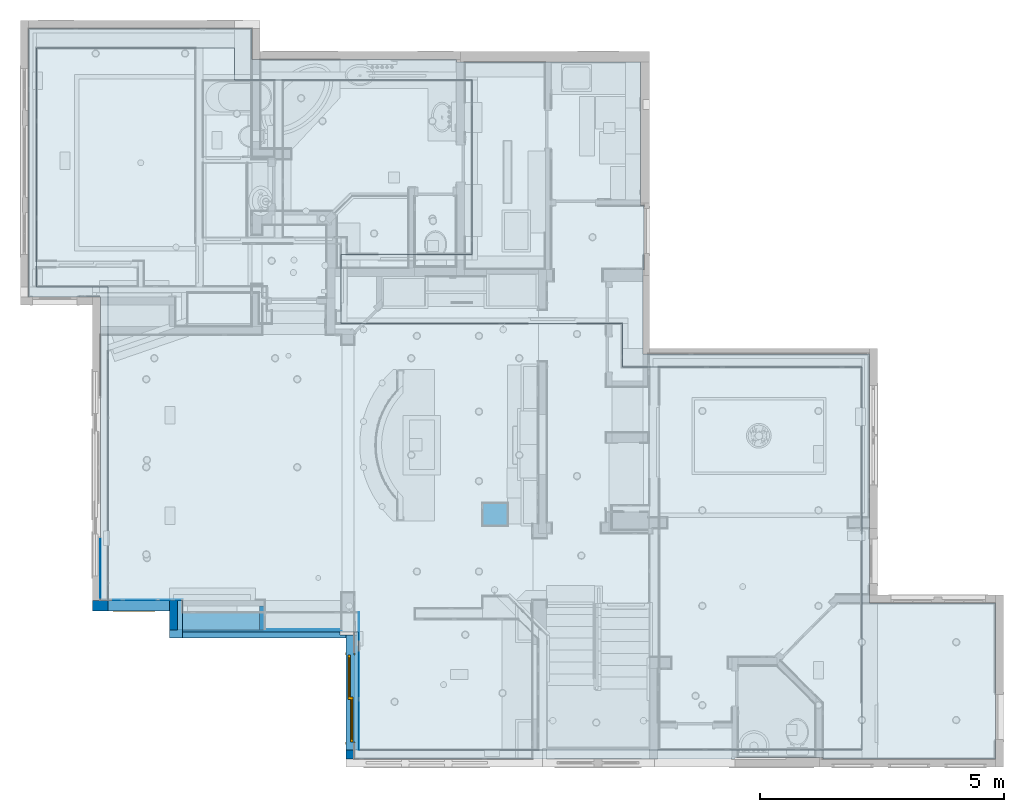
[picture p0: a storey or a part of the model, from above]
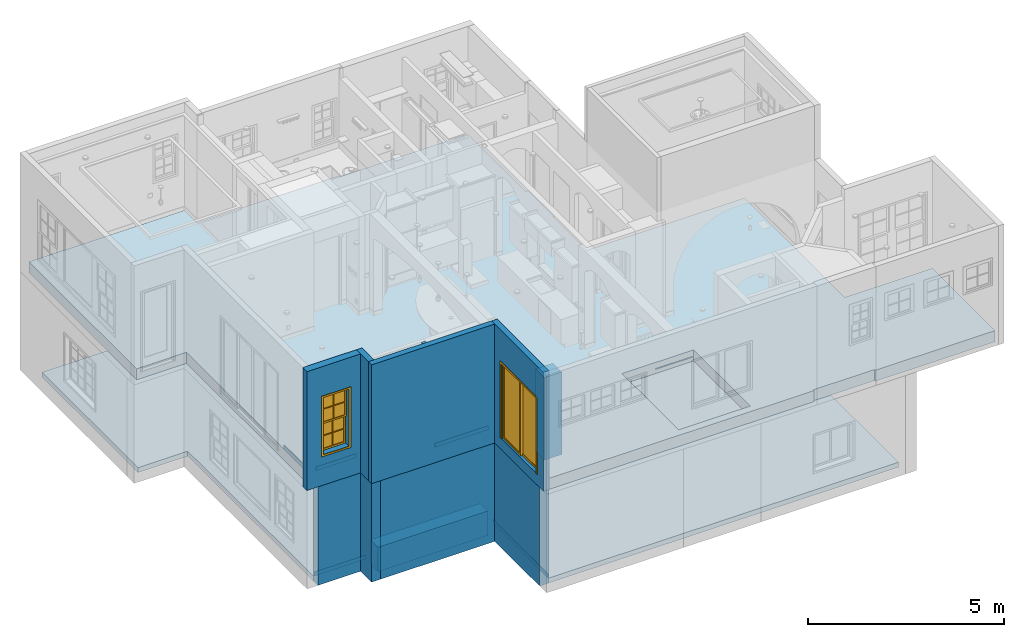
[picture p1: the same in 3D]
Properties of the parts of a building model (IFC2X3), part 1 of 2

# File
Description: ViewDefinition [CoordinationView_V2.0]
File name: Project Number
Time: 2024-05-09T19:01:35
Written by: The EXPRESS Data Manager Version 5.02.0100.07 : 28 Aug 2013
Made in: 21.1.90.15 - Exporter 21.1.90.15 - Alternate UI 21.1.90.15
Comment: STEP Physical File produced by: The EXPRESS Data Manager Version 5.02.0100.07 : 28 Aug 2013 * Module: EDMstepFileFactory/EDMstandAlone * Creation date: Thu May 09 19:01:35 2024 * Host: EDS0169-IshwarajKumbar * Database: C:\Users\User\AppData\Local\Temp\97b75f33-66e7-4dbd-bb98-ee40c45fb243\024e1fc7-9e23-4b7a-8644-b875dd77fc11\ifc * Database version: 5507 * Database creation date: Thu May 09 19:01:08 2024 * Schema: IFC2X3 * Model: DataRepository.ifc * Model creation date: Thu May 09 19:01:08 2024 * Header model: DataRepository.ifc_HeaderModel * Header model creation date: Thu May 09 19:01:08 2024 * EDMuser: sdai-user * EDMgroup: sdai-group * License ID and type: 5605 : Permanent license. Expiry date: * EDMstepFileFactory options: 020000

# IfcProject, Project Number
LongName: Project Name; Phase: Project Status

# IfcSite, Default
RefLatitude: 42, 21, 30, 344238; RefLongitude: -71, -3, -35, -194702; RefElevation: 0 ft
Pset_ProductRequirements - Category: Project Information

# IfcBuilding
Pset_BuildingCommon - NumberOfStoreys: 1
Pset_ProductRequirements - Category: Project Information

# IfcBuildingStorey: Level:1/4" Head, First floor
LongName: First floor; Elevation: 0 ft
Pset_AirSideSystemInformation - Name: First floor
Pset_ProductRequirements - Name: First floor; Category: Levels

# IfcBuildingElementProxy: Ceiling Duct:Ceiling Duct (10)
In: First floor
Type - Material: Default New Material
Type - Pset_BuildingElementProxyCommon - Reference: Ceiling Duct
Type - Pset_ProductRequirements - Category: Generic Models
Type - Pset_QuantityTakeOff - Reference: Ceiling Duct
Pset_BuildingElementProxyCommon - sets with these values: 2
Name (Ceiling Duct:Ceiling Duct:...) | Width (ft)
1502270 | 0.666667 | Pset_ProvisionForVoid - Height: 1.16667 ft; Depth: 0.0416667 ft
1502380 | 0.666667
1523142 | 0.666667
1523175 | 0.666667
1523206 | 0.666667
1523271 | 0.666667
1537971 | 0.75 | Pset_ProvisionForVoid - Height: 0.75 ft; Depth: 0.0416667 ft
1540716 | 0.666667
1568270 | 0.75
1568282 | 0.75

# IfcBuildingElementProxy: Floor Duct:Floor Duct (4)
In: First floor
Type - Material: Default New Material
Type - Pset_BuildingElementProxyCommon - Reference: Floor Duct
Type - Pset_ProductRequirements - Category: Generic Models
Type - Pset_QuantityTakeOff - Reference: Floor Duct
Pset_BuildingElementProxyCommon - sets with these values: 2
Name (Floor Duct:Floor Duct:...) | Width (ft)
1553929 | 0.666667 | Pset_ProvisionForVoid - Height: 0.666667 ft; Depth: 0.0416667 ft
1554124 | 0.666667
1580008 | 0.416667 | Pset_ProvisionForVoid - Height: 0.416667 ft; Depth: 0.0416667 ft
1580015 | 0.416667

# IfcBuildingElementProxy: Generic Models 10:Generic Models 10, Generic Models 10:Generic Models 10:1549112
In: First floor
Type - Material: Default New Material
Type - Pset_BuildingElementProxyCommon - Reference: Generic Models 10
Type - Pset_ProductRequirements - Category: Generic Models
Type - Pset_QuantityTakeOff - Reference: Generic Models 10
Pset_BuildingElementProxyCommon - sets with these values: 2
Pset_ProvisionForVoid - Width: 0.416667 ft; Height: 0.894398 ft; Depth: 0.416667 ft

# IfcBuildingElementProxy: Generic Models 11:Generic Models 11, Generic Models 11:Generic Models 11:1549126
In: First floor
Type - Material: Default New Material
Type - Pset_BuildingElementProxyCommon - Reference: Generic Models 11
Type - Pset_ProductRequirements - Category: Generic Models
Type - Pset_QuantityTakeOff - Reference: Generic Models 11
Pset_BuildingElementProxyCommon - sets with these values: 2

# IfcBuildingElementProxy: Generic Models 12:Generic Models 12, Generic Models 12:Generic Models 12:1549258
In: First floor
Type - Material: Default New Material
Type - Pset_BuildingElementProxyCommon - Reference: Generic Models 12
Type - Pset_ProductRequirements - Category: Generic Models
Type - Pset_QuantityTakeOff - Reference: Generic Models 12
Pset_BuildingElementProxyCommon - sets with these values: 2
Pset_ProvisionForVoid - Width: 1.45833 ft; Height: 6.91667 ft; Depth: 1.45833 ft

# IfcBuildingElementProxy: Generic Models 14:Generic Models 5, Generic Models 14:Generic Models 5:1550655
In: First floor
Type - Material: Default New Material
Type - Pset_BuildingElementProxyCommon - Reference: Generic Models 5
Type - Pset_ProductRequirements - Category: Generic Models
Type - Pset_QuantityTakeOff - Reference: Generic Models 5
Pset_BuildingElementProxyCommon - sets with these values: 2

# IfcBuildingElementProxy: Generic Models 15:Generic Models 15, Generic Models 15:Generic Models 15:1552585
In: First floor
Type - Material: Default New Material
Type - Pset_BuildingElementProxyCommon - Reference: Generic Models 15
Type - Pset_ProductRequirements - Category: Generic Models
Type - Pset_QuantityTakeOff - Reference: Generic Models 15
Pset_BuildingElementProxyCommon - sets with these values: 2

# IfcBuildingElementProxy: Generic Models 16:Generic Models 16, Generic Models 16:Generic Models 16:1554491
In: First floor
Type - Material: Default New Material
Type - Pset_BuildingElementProxyCommon - Reference: Generic Models 16
Type - Pset_ProductRequirements - Category: Generic Models
Type - Pset_QuantityTakeOff - Reference: Generic Models 16
Material: Default New Material, Glass
Pset_OpeningElementCommon - Reference: Generic Models 16; sets with these values: 2

# IfcBuildingElementProxy: Generic Models 20:Generic Models 20, Generic Models 20:Generic Models 20:1561079
In: First floor
Type - Material: Default New Material
Type - Pset_BuildingElementProxyCommon - Reference: Generic Models 20
Type - Pset_ProductRequirements - Category: Generic Models
Type - Pset_QuantityTakeOff - Reference: Generic Models 20
Pset_BuildingElementProxyCommon - sets with these values: 2

# IfcBuildingElementProxy: Generic Models 21:Generic Models 20, Generic Models 21:Generic Models 20:1561344
In: First floor
Type - Material: Default New Material
Type - Pset_BuildingElementProxyCommon - Reference: Generic Models 20
Type - Pset_ProductRequirements - Category: Generic Models
Type - Pset_QuantityTakeOff - Reference: Generic Models 20
Pset_BuildingElementProxyCommon - sets with these values: 2

# IfcBuildingElementProxy: Generic Models 22:Generic Models 22, Generic Models 22:Generic Models 22:1578308
In: First floor
Type - Material: Default New Material
Type - Pset_BuildingElementProxyCommon - Reference: Generic Models 22
Type - Pset_ProductRequirements - Category: Generic Models
Type - Pset_QuantityTakeOff - Reference: Generic Models 22
Pset_OpeningElementCommon - Reference: Generic Models 22; sets with these values: 2

# IfcBuildingElementProxy: Generic Models 23:Generic Models 16, Generic Models 23:Generic Models 16:1565228
In: First floor
Type - Material: Default New Material
Type - Pset_BuildingElementProxyCommon - Reference: Generic Models 16
Type - Pset_ProductRequirements - Category: Generic Models
Type - Pset_QuantityTakeOff - Reference: Generic Models 16
Pset_BuildingElementProxyCommon - sets with these values: 2
Pset_ProvisionForVoid - Width: 1.125 ft; Depth: 1.125 ft

# IfcBuildingElementProxy: Generic Models 24:Generic Models 24, Generic Models 24:Generic Models 24:1568251
In: First floor
Type - Material: Default New Material
Type - Pset_BuildingElementProxyCommon - Reference: Generic Models 24
Type - Pset_ProductRequirements - Category: Generic Models
Type - Pset_QuantityTakeOff - Reference: Generic Models 24
Pset_BuildingElementProxyCommon - sets with these values: 2
Pset_ProvisionForVoid - Width: 0.416667 ft; Depth: 0.416667 ft

# IfcBuildingElementProxy: Generic Models 25:Generic Models 23, Generic Models 25:Generic Models 23:1566142
In: First floor
Type - Material: Default New Material
Type - Pset_BuildingElementProxyCommon - Reference: Generic Models 23
Type - Pset_ProductRequirements - Category: Generic Models
Type - Pset_QuantityTakeOff - Reference: Generic Models 23
Pset_BuildingElementProxyCommon - sets with these values: 2

# IfcBuildingElementProxy: Generic Models 28:Generic Models 28, Generic Models 28:Generic Models 28:1579950
In: First floor
Type - Material: Default New Material
Type - Pset_BuildingElementProxyCommon - Reference: Generic Models 28
Type - Pset_ProductRequirements - Category: Generic Models
Type - Pset_QuantityTakeOff - Reference: Generic Models 28
Pset_BuildingElementProxyCommon - sets with these values: 2

# IfcBuildingElementProxy: Generic Models 29:Generic Models 28, Generic Models 29:Generic Models 28:1579967
In: First floor
Type - Material: Default New Material
Type - Pset_BuildingElementProxyCommon - Reference: Generic Models 28
Type - Pset_ProductRequirements - Category: Generic Models
Type - Pset_QuantityTakeOff - Reference: Generic Models 28
Pset_BuildingElementProxyCommon - sets with these values: 2

# IfcBuildingElementProxy: Generic Models 30:Generic Models 30, Generic Models 30:Generic Models 30:1590407
In: First floor
Type - Material: Default New Material
Type - Pset_BuildingElementProxyCommon - Reference: Generic Models 30
Type - Pset_ProductRequirements - Category: Generic Models
Type - Pset_QuantityTakeOff - Reference: Generic Models 30
Pset_BuildingElementProxyCommon - sets with these values: 2
Pset_ProvisionForVoid - Width: 6.91667 ft; Depth: 6.91667 ft

# IfcBuildingElementProxy: Generic Models 31:Generic Models 28, Generic Models 31:Generic Models 28:1590470
In: First floor
Type - Material: Default New Material
Type - Pset_BuildingElementProxyCommon - Reference: Generic Models 28
Type - Pset_ProductRequirements - Category: Generic Models
Type - Pset_QuantityTakeOff - Reference: Generic Models 28
Pset_BuildingElementProxyCommon - sets with these values: 2

# IfcBuildingElementProxy: Generic Models 32:Generic Models 28, Generic Models 32:Generic Models 28:1590484
In: First floor
Type - Material: Default New Material
Type - Pset_BuildingElementProxyCommon - Reference: Generic Models 28
Type - Pset_ProductRequirements - Category: Generic Models
Type - Pset_QuantityTakeOff - Reference: Generic Models 28
Pset_BuildingElementProxyCommon - sets with these values: 2

# IfcBuildingElementProxy: Generic Models 33:Generic Models 28, Generic Models 33:Generic Models 28:1590457
In: First floor
Type - Material: Default New Material
Type - Pset_BuildingElementProxyCommon - Reference: Generic Models 28
Type - Pset_ProductRequirements - Category: Generic Models
Type - Pset_QuantityTakeOff - Reference: Generic Models 28
Pset_BuildingElementProxyCommon - sets with these values: 2

# IfcBuildingElementProxy: Generic Models 34:Generic Models 28, Generic Models 34:Generic Models 28:1593320
In: First floor
Type - Material: Default New Material
Type - Pset_BuildingElementProxyCommon - Reference: Generic Models 28
Type - Pset_ProductRequirements - Category: Generic Models
Type - Pset_QuantityTakeOff - Reference: Generic Models 28
Pset_BuildingElementProxyCommon - sets with these values: 2

# IfcBuildingElementProxy: Generic Models 35:Generic Models 28, Generic Models 35:Generic Models 28:1593336
In: First floor
Type - Material: Default New Material
Type - Pset_BuildingElementProxyCommon - Reference: Generic Models 28
Type - Pset_ProductRequirements - Category: Generic Models
Type - Pset_QuantityTakeOff - Reference: Generic Models 28
Pset_BuildingElementProxyCommon - sets with these values: 2

# IfcBuildingElementProxy: Generic Models 36:Generic Models 28, Generic Models 36:Generic Models 28:1593352
In: First floor
Type - Material: Default New Material
Type - Pset_BuildingElementProxyCommon - Reference: Generic Models 28
Type - Pset_ProductRequirements - Category: Generic Models
Type - Pset_QuantityTakeOff - Reference: Generic Models 28
Pset_BuildingElementProxyCommon - sets with these values: 2
Pset_ProvisionForVoid - Width: 4.08367 ft; Depth: 4.08367 ft

# IfcBuildingElementProxy: Generic Models 37:Generic Models 37, Generic Models 37:Generic Models 37:1600293
In: First floor
Type - Material: Default New Material
Type - Pset_BuildingElementProxyCommon - Reference: Generic Models 37
Type - Pset_ProductRequirements - Category: Generic Models
Type - Pset_QuantityTakeOff - Reference: Generic Models 37
Pset_BuildingElementProxyCommon - sets with these values: 2

# IfcBuildingElementProxy: Generic Models 38:Generic Models 38, Generic Models 38:Generic Models 38:1608313
In: First floor
Type - Material: Default New Material
Type - Pset_BuildingElementProxyCommon - Reference: Generic Models 38
Type - Pset_ProductRequirements - Category: Generic Models
Type - Pset_QuantityTakeOff - Reference: Generic Models 38
Pset_BuildingElementProxyCommon - sets with these values: 2
Pset_ProvisionForVoid - Width: 0.625 ft; Height: 10.5833 ft; Depth: 0.625 ft

# IfcBuildingElementProxy: Generic Models 3:Generic Models 3, Generic Models 3:Generic Models 3:1515765
In: First floor
Type - Material: Glass
Type - Pset_BuildingElementProxyCommon - Reference: Generic Models 3
Type - Pset_ProductRequirements - Category: Generic Models
Type - Pset_QuantityTakeOff - Reference: Generic Models 3
Pset_BuildingElementProxyCommon - sets with these values: 2
Pset_ProvisionForVoid - Width: 6.83333 ft; Depth: 6.83333 ft

# IfcBuildingElementProxy: Generic Models 47:Generic Models 5, Generic Models 47:Generic Models 5:1632938
In: First floor
Type - Material: Default New Material
Type - Pset_BuildingElementProxyCommon - Reference: Generic Models 5
Type - Pset_ProductRequirements - Category: Generic Models
Type - Pset_QuantityTakeOff - Reference: Generic Models 5
Pset_BuildingElementProxyCommon - sets with these values: 2

# IfcBuildingElementProxy: Generic Models 4:Generic Models 4, Generic Models 4:Generic Models 4:1523625
In: First floor
Type - Material: Default New Material
Type - Pset_BuildingElementProxyCommon - Reference: Generic Models 4
Type - Pset_ProductRequirements - Category: Generic Models
Type - Pset_QuantityTakeOff - Reference: Generic Models 4
Pset_OpeningElementCommon - Reference: Generic Models 4; sets with these values: 2

# IfcBuildingElementProxy: Generic Models 52:Generic Models 52, Generic Models 52:Generic Models 52:1640525
In: First floor
Type - Material: Default New Material
Type - Pset_BuildingElementProxyCommon - Reference: Generic Models 52
Type - Pset_ProductRequirements - Category: Generic Models
Type - Pset_QuantityTakeOff - Reference: Generic Models 52
Pset_BuildingElementProxyCommon - sets with these values: 2
Pset_ProvisionForVoid - Width: 2.08333 ft; Depth: 2.08333 ft

# IfcBuildingElementProxy: Generic Models 56:Generic Models 56, Generic Models 56:Generic Models 56:1644916
In: First floor
Type - Material: Default New Material
Type - Pset_BuildingElementProxyCommon - Reference: Generic Models 56
Type - Pset_ProductRequirements - Category: Generic Models
Type - Pset_QuantityTakeOff - Reference: Generic Models 56
Pset_BuildingElementProxyCommon - sets with these values: 2
Pset_ProvisionForVoid - Width: 0.0833333 ft; Depth: 0.0833333 ft

# IfcBuildingElementProxy: Generic Models 59:Generic Models 59, Generic Models 59:Generic Models 59:1646296
In: First floor
Type - Material: Default New Material
Type - Pset_BuildingElementProxyCommon - Reference: Generic Models 59
Type - Pset_ProductRequirements - Category: Generic Models
Type - Pset_QuantityTakeOff - Reference: Generic Models 59
Pset_BuildingElementProxyCommon - sets with these values: 2
Pset_ProvisionForVoid - Width: 1.16667 ft; Height: 1.08333 ft; Depth: 1.16667 ft

# IfcBuildingElementProxy: Generic Models 60:Generic Models 59, Generic Models 60:Generic Models 59:1647426
In: First floor
Type - Material: Default New Material
Type - Pset_BuildingElementProxyCommon - Reference: Generic Models 59
Type - Pset_ProductRequirements - Category: Generic Models
Type - Pset_QuantityTakeOff - Reference: Generic Models 59
Pset_BuildingElementProxyCommon - sets with these values: 2
Pset_ProvisionForVoid - Width: 1.16667 ft; Height: 1.08333 ft; Depth: 1.16667 ft

# IfcBuildingElementProxy: Generic Models 61:Generic Models 61, Generic Models 61:Generic Models 61:1657220
In: First floor
Type - Material: Default New Material
Type - Pset_BuildingElementProxyCommon - Reference: Generic Models 61
Type - Pset_ProductRequirements - Category: Generic Models
Type - Pset_QuantityTakeOff - Reference: Generic Models 61
Pset_BuildingElementProxyCommon - sets with these values: 2
Pset_ProvisionForVoid - Width: 1 ft; Height: 2 ft; Depth: 1 ft

# IfcBuildingElementProxy: Generic Models 62:Generic Models 62, Generic Models 62:Generic Models 62:1670910
In: First floor
Type - Material: <Unnamed>
Type - Pset_BuildingElementProxyCommon - Reference: Generic Models 62
Type - Pset_ProductRequirements - Category: Generic Models
Type - Pset_QuantityTakeOff - Reference: Generic Models 62
Pset_OpeningElementCommon - Reference: Generic Models 62; sets with these values: 2

# IfcBuildingElementProxy: Generic Models 64:Generic Models 64, Generic Models 64:Generic Models 64:1680121
In: First floor
Type - Material: Default New Material
Type - Pset_BuildingElementProxyCommon - Reference: Generic Models 64
Type - Pset_ProductRequirements - Category: Generic Models
Type - Pset_QuantityTakeOff - Reference: Generic Models 64
Pset_BuildingElementProxyCommon - sets with these values: 2
Pset_ProvisionForVoid - Width: 0.0416667 ft; Height: 4 ft; Depth: 0.0416667 ft

# IfcBuildingElementProxy: Generic Models 65:Generic Models 65, Generic Models 65:Generic Models 65:1687296
In: First floor
Type - Material: Default New Material
Type - Pset_BuildingElementProxyCommon - Reference: Generic Models 65
Type - Pset_ProductRequirements - Category: Generic Models
Type - Pset_QuantityTakeOff - Reference: Generic Models 65
Pset_BuildingElementProxyCommon - sets with these values: 2
Pset_ProvisionForVoid - Width: 0.0833333 ft; Depth: 0.0833333 ft

# IfcBuildingElementProxy: Generic Models 66:Generic Models 66, Generic Models 66:Generic Models 66:1692336
In: First floor
Type - Material: Default New Material
Type - Pset_BuildingElementProxyCommon - Reference: Generic Models 66
Type - Pset_ProductRequirements - Category: Generic Models
Type - Pset_QuantityTakeOff - Reference: Generic Models 66
Pset_BuildingElementProxyCommon - sets with these values: 2
Pset_ProvisionForVoid - Width: 1.16667 ft; Height: 2.08333 ft; Depth: 1.16667 ft

# IfcBuildingElementProxy: Generic Models 67:Generic Models 67, Generic Models 67:Generic Models 67:1693115
In: First floor
Type - Material: Default New Material
Type - Pset_BuildingElementProxyCommon - Reference: Generic Models 67
Type - Pset_ProductRequirements - Category: Generic Models
Type - Pset_QuantityTakeOff - Reference: Generic Models 67
Pset_BuildingElementProxyCommon - sets with these values: 2
Pset_ProvisionForVoid - Width: 3.25 ft; Depth: 3.25 ft

# IfcBuildingElementProxy: Generic Models 68:Generic Models 68, Generic Models 68:Generic Models 68:1696514
In: First floor
Type - Material: Default New Material
Type - Pset_BuildingElementProxyCommon - Reference: Generic Models 68
Type - Pset_ProductRequirements - Category: Generic Models
Type - Pset_QuantityTakeOff - Reference: Generic Models 68
Pset_BuildingElementProxyCommon - sets with these values: 2
Pset_ProvisionForVoid - Width: 1.58333 ft; Height: 1.5 ft; Depth: 1.58333 ft

# IfcBuildingElementProxy: Generic Models 7:Generic Models 7, Generic Models 7:Generic Models 7:1549020
In: First floor
Type - Material: Default New Material
Type - Pset_BuildingElementProxyCommon - Reference: Generic Models 7
Type - Pset_ProductRequirements - Category: Generic Models
Type - Pset_QuantityTakeOff - Reference: Generic Models 7
Pset_BuildingElementProxyCommon - sets with these values: 2
Pset_ProvisionForVoid - Width: 0.0416667 ft; Depth: 0.0416667 ft

# IfcBuildingElementProxy: Generic Models 8:Generic Models 8, Generic Models 8:Generic Models 8:1549080
In: First floor
Type - Material: Default New Material
Type - Pset_BuildingElementProxyCommon - Reference: Generic Models 8
Type - Pset_ProductRequirements - Category: Generic Models
Type - Pset_QuantityTakeOff - Reference: Generic Models 8
Pset_BuildingElementProxyCommon - sets with these values: 2
Pset_ProvisionForVoid - Width: 0.416667 ft; Height: 0.908704 ft; Depth: 0.416667 ft

# IfcBuildingElementProxy: Generic Models 9:Generic Models 9, Generic Models 9:Generic Models 9:1549096
In: First floor
Type - Material: Default New Material
Type - Pset_BuildingElementProxyCommon - Reference: Generic Models 9
Type - Pset_ProductRequirements - Category: Generic Models
Type - Pset_QuantityTakeOff - Reference: Generic Models 9
Pset_BuildingElementProxyCommon - sets with these values: 2
Pset_ProvisionForVoid - Width: 0.416667 ft; Height: 0.908704 ft; Depth: 0.416667 ft

# IfcBuildingElementProxy: Generic_01:Generic_01 (2)
In: First floor
Type - Material: Default New Material
Type - Pset_BuildingElementProxyCommon - Reference: Generic_01
Type - Pset_ProductRequirements - Category: Generic Models
Type - Pset_QuantityTakeOff - Reference: Generic_01
Pset_BuildingElementProxyCommon - sets with these values: 2
Pset_ProvisionForVoid - Width: 1.375 ft; Height: 0.666667 ft
Name (Generic_01:Generic_01:...)
1546603 | Pset_ProvisionForVoid - Depth: 0.666667 ft
1593018

# IfcBuildingElementProxy: Generic_02:Generic_02 (4)
In: First floor
Type - Material: Default New Material
Type - Pset_BuildingElementProxyCommon - Reference: Generic_02
Type - Pset_ProductRequirements - Category: Generic Models
Type - Pset_QuantityTakeOff - Reference: Generic_02
Pset_BuildingElementProxyCommon - sets with these values: 2
Pset_ProvisionForVoid - Height: 0.145833 ft
Name (Generic_02:Generic_02:...) | Width (ft) | Depth (ft)
1545830 | 1.16667 | 0.0208333
1551174 | 1.16667
1565230 | 0.75 | 0.0208333
1574967 | 0.75 | 0.0208333

# IfcBuildingElementProxy: Generic_03:Generic_03, Generic_03:Generic_03:1589796
In: First floor
Type - Material: Default New Material
Type - Pset_BuildingElementProxyCommon - Reference: Generic_03
Type - Pset_ProductRequirements - Category: Generic Models
Type - Pset_QuantityTakeOff - Reference: Generic_03
Pset_BuildingElementProxyCommon - sets with these values: 2
Pset_ProvisionForVoid - Width: 0.416667 ft; Height: 0.416667 ft; Depth: 0.0416667 ft

# IfcBuildingElementProxy: Specialty Equipment 1:Specialty Equipment 1, Specialty Equipment 1:Specialty Equipment 1:1546123
In: First floor
Type - Material: Default New Material
Type - Pset_BuildingElementProxyCommon - Reference: Specialty Equipment 1
Type - Pset_ProductRequirements - Category: Specialty Equipment
Type - Pset_QuantityTakeOff - Reference: Specialty Equipment 1
Pset_BuildingElementProxyCommon - sets with these values: 2
Pset_ProvisionForVoid - Width: 0.230472 ft; Depth: 0.230472 ft

# IfcBuildingElementProxy: Specialty Equipment 2:Specialty Equipment 2, Specialty Equipment 2:Specialty Equipment 2:1698001
In: First floor
Type - Material: Default New Material
Type - Pset_BuildingElementProxyCommon - Reference: Specialty Equipment 2
Type - Pset_ProductRequirements - Category: Specialty Equipment
Type - Pset_QuantityTakeOff - Reference: Specialty Equipment 2
Pset_BuildingElementProxyCommon - sets with these values: 2

# IfcBuildingElementProxy: Specialty Equipment_1:Specialty Equipment_1 (12)
In: First floor
Type - Material: Default New Material
Type - Pset_BuildingElementProxyCommon - Reference: Specialty Equipment_1
Type - Pset_ProductRequirements - Category: Specialty Equipment
Type - Pset_QuantityTakeOff - Reference: Specialty Equipment_1
Pset_BuildingElementProxyCommon - sets with these values: 2
Name (Specialty Equipment_1:Specialty Equipment_1:...) | Width (ft) | Height (ft) | Depth (ft)
1534345 | 0.5 | 0.416667 | 0.416667
1593358 | 4 | 2.83333 | 2.83333
1623707 | 0.208333 | 0.0416667 | 0.0416667
1643836 | 0.5 | 0.333333 | 0.333333
1644112 | 0.5 | 0.666667 | 0.666667
1644243 | 0.166667 | 0.166667 | 0.166667
1645875 | 0.5 | 0.375 | 0.375
1649110 | 2.16667 | 3.33333 | 3.33333
1649419 | 2.16667 | 3.33333
1653499 | 0.166667 | 0.416667 | 0.416667
1653652 | 0.666667 | 0.416667 | 0.416667
1654167 | 2 | 2.45833 | 2.45833

# IfcBuildingElementProxy: Specialty Equipment_2:Specialty Equipment_2 (4)
In: First floor
Type - Material: Default New Material
Type - Pset_BuildingElementProxyCommon - Reference: Specialty Equipment_2
Type - Pset_ProductRequirements - Category: Specialty Equipment
Type - Pset_QuantityTakeOff - Reference: Specialty Equipment_2
Pset_BuildingElementProxyCommon - sets with these values: 2
Name (Specialty Equipment_2:Specialty Equipment_2:...) | Width (ft) | Height (ft) = Depth (ft)
1590512 | 3.16667 | 5.75
1593223 | 2.75 | 0.916667
1593226 | 2.75 | 2.33333
1593228 | 2.75 | 1.58333

# IfcBuildingElementProxy: Specialty Equipment_4:Specialty Equipment_4 (6)
In: First floor
Type - Material: Default New Material
Type - Pset_BuildingElementProxyCommon - Reference: Specialty Equipment_4
Type - Pset_ProductRequirements - Category: Specialty Equipment
Type - Pset_QuantityTakeOff - Reference: Specialty Equipment_4
Pset_BuildingElementProxyCommon - sets with these values: 2
Name (Specialty Equipment_4:Specialty Equipment_4:...)
1534789 | Pset_ProvisionForVoid - Width: 0.0416667 ft; Depth: 0.0416667 ft
1535804
1540086
1559416
1576774 | Pset_ProvisionForVoid - Width: 0.0416667 ft; Depth: 0.0416667 ft
1577019

# IfcBuildingElementProxy: Switch 15:Switch 15 (9)
In: First floor
Type - Material: Default New Material
Type - Pset_BuildingElementProxyCommon - Reference: Switch 15
Type - Pset_ProductRequirements - Category: Electrical Fixtures
Type - Pset_QuantityTakeOff - Reference: Switch 15
Pset_BuildingElementProxyCommon - sets with these values: 2
Name (Switch 15:Switch 15:...)
1509897 | Pset_ProvisionForVoid - Width: 0.291667 ft; Height: 0.416667 ft; Depth: 0.291667 ft
1543753
1543996
1566214
1568121
1590492
1590504 | Pset_ProvisionForVoid - Width: 0.291667 ft; Height: 0.0416667 ft; Depth: 0.291667 ft
1592945
1593269

# IfcBuildingElementProxy: Switch 18:Switch 18 (4)
In: First floor
Type - Material: Default New Material
Type - Pset_BuildingElementProxyCommon - Reference: Switch 18
Type - Pset_ProductRequirements - Category: Electrical Fixtures
Type - Pset_QuantityTakeOff - Reference: Switch 18
Pset_BuildingElementProxyCommon - sets with these values: 2
Name (Switch 18:Switch 18:...)
1572272 | Pset_ProvisionForVoid - Width: 0.416667 ft; Height: 0.291667 ft; Depth: 0.416667 ft
1579968
1590443
1590503 | Pset_ProvisionForVoid - Width: 0.416667 ft; Height: 0.0416667 ft; Depth: 0.416667 ft

# IfcBuildingElementProxy: Switch 1:Switch 1 (37)
In: First floor
Type - Material: Default New Material
Type - Pset_BuildingElementProxyCommon - Reference: Switch 1
Type - Pset_ProductRequirements - Category: Electrical Fixtures
Type - Pset_QuantityTakeOff - Reference: Switch 1
Pset_BuildingElementProxyCommon - sets with these values: 2
Name (Switch 1:Switch 1:...) | Width (ft) | Height (ft)
1500248 | 0.291667 | 0.416667 | Pset_ProvisionForVoid - Depth: 0.416667 ft
1500756 | 0.291667 | 0.416667
1501134 | 0.291667 | 0.416667
1501219 | 0.291667 | 0.416667
1501973 | 0.291667 | 0.416667
1508420 | 0.291667 | 0.416667
1533359 | 0.291667 | 0.416667
1534123 | 0.291667 | 0.416667
1535636 | 0.291667 | 0.416667
1536600 | 0.291667 | 0.416667
1538305 | 0.291667 | 0.416667
1538381 | 0.291667 | 0.416667
1540579 | 0.291667 | 0.416667
1543512 | 0.291667 | 0.416667
1544074 | 0.291667 | 0.416667
1544209 | 0.291667 | 0.416667
1544240 | 0.291667 | 0.416667
1544276 | 0.291667 | 0.416667
1544526 | 0.291667 | 0.416667
1544649 | 0.291667 | 0.416667
1544737 | 0.291667 | 0.416667
1546165 | 0.291667 | 0.416667
1546320 | 0.291667 | 0.416667
1551175 | 0.291667 | 0.416667
1551178 | 0.291667 | 0.416667
1551225 | 0.291667 | 0.416667
1551419 | 0.291667 | 0.416667
1556863 | 0.291667 | 0.416667
1557131 | 0.291667 | 0.416667
1578468 | 0.291667 | 0.416667
1578781 | 0.291667 | 0.416667
1579326 | 0.291667 | 0.416667
1590427 | 0.291667 | 0.416667
1590428 | 0.291667 | 0.416667
1590429 | 0.291667 | 0.416667
1590490 | 0.458333 | 0.25 | Pset_ProvisionForVoid - Depth: 0.25 ft
1590499 | 0.458333 | 0.25

# IfcBuildingElementProxy: Switch 20:Switch 20, Switch 20:Switch 20:1509279
In: First floor
Type - Material: Default New Material
Type - Pset_BuildingElementProxyCommon - Reference: Switch 20
Type - Pset_ProductRequirements - Category: Electrical Fixtures
Type - Pset_QuantityTakeOff - Reference: Switch 20
Pset_BuildingElementProxyCommon - sets with these values: 2
Pset_ProvisionForVoid - Width: 0.416667 ft; Height: 0.583333 ft; Depth: 0.416667 ft

# IfcBuildingElementProxy: Switch 22:Switch 22 (8)
In: First floor
Type - Material: Default New Material
Type - Pset_BuildingElementProxyCommon - Reference: Switch 22
Type - Pset_ProductRequirements - Category: Electrical Fixtures
Type - Pset_QuantityTakeOff - Reference: Switch 22
Pset_BuildingElementProxyCommon - sets with these values: 2
Name (Switch 22:Switch 22:...)
1507004 | Pset_ProvisionForVoid - Width: 0.416667 ft; Height: 0.708333 ft; Depth: 0.416667 ft
1545878
1547098
1556649
1568123
1571976
1579429
1590430

# IfcBuildingElementProxy: Switch 3:Switch 3 (10)
In: First floor
Type - Material: Default New Material
Type - Pset_BuildingElementProxyCommon - Reference: Switch 3
Type - Pset_ProductRequirements - Category: Electrical Fixtures
Type - Pset_QuantityTakeOff - Reference: Switch 3
Pset_BuildingElementProxyCommon - sets with these values: 2
Name (Switch 3:Switch 3:...)
1535327 | Pset_ProvisionForVoid - Width: 0.416667 ft; Height: 0.291667 ft; Depth: 0.416667 ft
1536376
1538126
1543306
1546375
1551740
1565232
1565233
1575068
1578659

# IfcBuildingElementProxy: Switch 4:Switch 4 (50)
In: First floor
Type - Material: Default New Material
Type - Pset_BuildingElementProxyCommon - Reference: Switch 4
Type - Pset_ProductRequirements - Category: Electrical Fixtures
Type - Pset_QuantityTakeOff - Reference: Switch 4
Pset_BuildingElementProxyCommon - sets with these values: 2
Name (Switch 4:Switch 4:...)
1499978 | Pset_ProvisionForVoid - Width: 0.416667 ft; Height: 0.291667 ft; Depth: 0.416667 ft
1500459
1501395
1501552
1501702
1506937
1506939
1506940
1507204
1507495
1507695
1508319
1508593
1508731
1508896
1509063
1509492
1509675
1533098
1534947
1535218
1535815
1536016
1536137
1538750
1540161
1540484
1543122
1545832
1547252
1551177
1551179
1551181
1551743
1553709
1553844
1554188
1556535
1556783
1565183
1565231
1574969
1577151
1579085
1579500
1580010
1580013
1580019
1594570
1594822

# IfcBuildingElementProxy: Switch 6:Switch 6 (14)
In: First floor
Type - Material: Default New Material
Type - Pset_BuildingElementProxyCommon - Reference: Switch 6
Type - Pset_ProductRequirements - Category: Electrical Fixtures
Type - Pset_QuantityTakeOff - Reference: Switch 6
Pset_BuildingElementProxyCommon - sets with these values: 2
Name (Switch 6:Switch 6:...)
1533406 | Pset_ProvisionForVoid - Width: 0.416667 ft; Height: 0.416667 ft; Depth: 0.416667 ft
1534238
1537489
1551356
1553510
1556968
1559630
1560495
1565185
1568283
1569646
1575067
1579565
1590501

# IfcBuildingElementProxy: Wall Duct:Wall Duct (5)
In: First floor
Type - Material: Default New Material
Type - Pset_BuildingElementProxyCommon - Reference: Wall Duct
Type - Pset_ProductRequirements - Category: Generic Models
Type - Pset_QuantityTakeOff - Reference: Wall Duct
Pset_BuildingElementProxyCommon - sets with these values: 2
Name (Wall Duct:Wall Duct:...) | Width (ft) | Height (ft) | Depth (ft)
1532870 | 2.75 | 0.583333 | 0.583333
1540217 | 1 | 0.666667 | 0.666667
1560153 | 2.66667 | 0.833333 | 0.833333
1593266 | 1.375 | 0.416667 | 0.416667
1653343 | 2.75 | 0.583333

# IfcBuildingElementProxy: Wall void 1 :Wall void 1, Wall void 1 :Wall void 1:1651944
In: First floor
Type - Material: Default New Material
Type - Pset_BuildingElementProxyCommon - Reference: Wall void 1
Type - Pset_ProductRequirements - Category: Generic Models
Type - Pset_QuantityTakeOff - Reference: Wall void 1
Pset_OpeningElementCommon - Reference: Wall void 1; sets with these values: 2

# IfcColumn: M_Rectangular Column:475 x 610mm, M_Rectangular Column:475 x 610mm:1609656
In: First floor
Type - PredefinedType: COLUMN; Material: Default New Material
Type - Pset_ColumnCommon - IsExternal: no; Reference: 475 x 610mm
Type - Pset_ProductRequirements - Category: Columns
Type - Pset_QuantityTakeOff - Reference: 475 x 610mm
Type - Pset_ReinforcementBarPitchOfColumn - Reference: 475 x 610mm
Pset_QuantityTakeOff - sets with these values: 2

# IfcCovering: Compound Ceiling:Ceiling_1.5", Compound Ceiling:Ceiling_1.5":1575162
In: First floor
Type - PredefinedType: CEILING
Type - Pset_CoveringCommon - Reference: Ceiling_1.5"; TotalThickness: 0.125 ft
Type - Pset_ElementShading - Roughness: 1 ft
Type - Pset_ProductRequirements - Category: Ceilings
Type - Pset_QuantityTakeOff - Reference: Ceiling_1.5"
Classification: C3030210 Suspended Ceilings - Acoustical (Uniformat); Material: Default New Material 0.125 ft

# IfcCovering: Compound Ceiling:Ceiling_1.5" 1, Compound Ceiling:Ceiling_1.5" 1:1579975
In: First floor
Type - PredefinedType: CEILING
Type - Pset_CoveringCommon - Reference: Ceiling_1.5" 1; TotalThickness: 0.125 ft
Type - Pset_ElementShading - Roughness: 1 ft
Type - Pset_ProductRequirements - Category: Ceilings
Type - Pset_QuantityTakeOff - Reference: Ceiling_1.5" 1
Classification: C3030210 Suspended Ceilings - Acoustical (Uniformat); Material: Default New Material 0.125 ft

# IfcCovering: Compound Ceiling:Ceiling_12", Compound Ceiling:Ceiling_12":1575072
In: First floor
Type - PredefinedType: CEILING
Type - Pset_CoveringCommon - Reference: Ceiling_12"; TotalThickness: 1 ft
Type - Pset_ElementShading - Roughness: 1 ft
Type - Pset_ProductRequirements - Category: Ceilings
Type - Pset_QuantityTakeOff - Reference: Ceiling_12"
Classification: C3030210 Suspended Ceilings - Acoustical (Uniformat); Material: Default New Material 1 ft

# IfcCovering: Compound Ceiling:Ceiling_13.5", Compound Ceiling:Ceiling_13.5":1456698
In: First floor
Type - PredefinedType: CEILING
Type - Pset_CoveringCommon - Reference: Ceiling_13.5"; TotalThickness: 1.125 ft
Type - Pset_ElementShading - Roughness: 1 ft
Type - Pset_ProductRequirements - Category: Ceilings
Type - Pset_QuantityTakeOff - Reference: Ceiling_13.5"
Classification: C3030210 Suspended Ceilings - Acoustical (Uniformat); Material: Default New Material 1.125 ft

# IfcCovering: Compound Ceiling:Ceiling_14", Compound Ceiling:Ceiling_14":1560792
In: First floor
Type - PredefinedType: CEILING
Type - Pset_CoveringCommon - Reference: Ceiling_14"; TotalThickness: 1.16667 ft
Type - Pset_ElementShading - Roughness: 1 ft
Type - Pset_ProductRequirements - Category: Ceilings
Type - Pset_QuantityTakeOff - Reference: Ceiling_14"
Classification: C3030210 Suspended Ceilings - Acoustical (Uniformat); Material: Default New Material 1.16667 ft

# IfcCovering: Compound Ceiling:Ceiling_2", Compound Ceiling:Ceiling_2":1557191
In: First floor
Type - PredefinedType: CEILING
Type - Pset_CoveringCommon - Reference: Ceiling_2"; TotalThickness: 0.166667 ft
Type - Pset_ElementShading - Roughness: 1 ft
Type - Pset_ProductRequirements - Category: Ceilings
Type - Pset_QuantityTakeOff - Reference: Ceiling_2"
Classification: C3030210 Suspended Ceilings - Acoustical (Uniformat); Material: Default New Material 0.166667 ft

# IfcCovering: Compound Ceiling:Ceiling_5.25", Compound Ceiling:Ceiling_5.25":1568254
In: First floor
Type - PredefinedType: CEILING
Type - Pset_CoveringCommon - Reference: Ceiling_5.25"; TotalThickness: 0.4375 ft
Type - Pset_ElementShading - Roughness: 1 ft
Type - Pset_ProductRequirements - Category: Ceilings
Type - Pset_QuantityTakeOff - Reference: Ceiling_5.25"
Classification: C3030210 Suspended Ceilings - Acoustical (Uniformat); Material: Default New Material 0.4375 ft

# IfcCovering: Compound Ceiling:Ceiling_6" (3)
In: First floor
Type - PredefinedType: CEILING
Type - Pset_CoveringCommon - Reference: Ceiling_6"; TotalThickness: 0.5 ft
Type - Pset_ElementShading - Roughness: 1 ft
Type - Pset_ProductRequirements - Category: Ceilings
Type - Pset_QuantityTakeOff - Reference: Ceiling_6"
Classification: C3030210 Suspended Ceilings - Acoustical (Uniformat); Material: Default New Material 0.5 ft
Name (Compound Ceiling:Ceiling_6":...)
1525813
1550592
1550622

# IfcDistributionPort (75)
Description: Flow
Name | FlowDirection
Port_1476054 | SINK
Port_1476054 | SOURCE
Port_1505726 | SOURCEANDSINK
Port_1505889 | SOURCEANDSINK
Port_1505928 | SOURCEANDSINK
Port_1505938 | SOURCEANDSINK
Port_1506017 | SOURCEANDSINK
Port_1506018 | SOURCEANDSINK
Port_1506019 | SOURCEANDSINK
Port_1506020 | SOURCEANDSINK
Port_1513958 | SINK
Port_1513958 | SOURCE
Port_1513960 | SOURCE
Port_1513960 | SINK
Port_1521985 | SOURCEANDSINK
Port_1522158 | SOURCEANDSINK
Port_1522220 | SOURCEANDSINK
Port_1522267 | SOURCEANDSINK
Port_1522268 | SOURCEANDSINK
Port_1522298 | SOURCEANDSINK
Port_1522343 | SOURCEANDSINK
Port_1522373 | SOURCEANDSINK
Port_1522422 | SOURCEANDSINK
Port_1522477 | SOURCEANDSINK
Port_1522552 | SOURCEANDSINK
Port_1522629 | SOURCEANDSINK
Port_1522698 | SOURCEANDSINK
Port_1522757 | SOURCEANDSINK
Port_1522875 | SOURCEANDSINK
Port_1522915 | SOURCEANDSINK
Port_1522916 | SOURCEANDSINK
Port_1522943 | SOURCEANDSINK
Port_1525877 | SOURCEANDSINK
Port_1531003 | SOURCEANDSINK
Port_1536648 | SOURCEANDSINK
Port_1551746 | SOURCEANDSINK
Port_1551825 | SOURCEANDSINK
Port_1552003 | SOURCEANDSINK
Port_1559209 | SOURCEANDSINK
Port_1561095 | SOURCEANDSINK
Port_1563279 | SOURCEANDSINK
Port_1575069 | SOURCEANDSINK
Port_1575128 | SOURCEANDSINK
Port_1575129 | SOURCEANDSINK
Port_1575130 | SOURCEANDSINK
Port_1593979 | SOURCEANDSINK
Port_1594397 | SOURCEANDSINK
Port_1594443 | SOURCEANDSINK
Port_1594473 | SOURCEANDSINK
Port_1608332 | SOURCEANDSINK
Port_1608445 | SOURCEANDSINK
Port_1608591 | SOURCEANDSINK
Port_1608735 | SOURCEANDSINK
Port_1635850 | SOURCEANDSINK
Port_1643636 | SOURCEANDSINK
Port_1643797 | SOURCEANDSINK
Port_1647569 | SOURCEANDSINK
Port_1647618 | SOURCEANDSINK
Port_1654337 | SOURCEANDSINK
Port_1666624 | SOURCEANDSINK
Port_1666771 | SOURCEANDSINK
Port_1668183 | SOURCEANDSINK
Port_1668241 | SOURCEANDSINK
Port_1668289 | SOURCEANDSINK
Port_1668351 | SOURCEANDSINK
Port_1668442 | SOURCEANDSINK
Port_1668620 | SOURCEANDSINK
Port_1668669 | SOURCEANDSINK
Port_1668714 | SOURCEANDSINK
Port_1668768 | SOURCEANDSINK
Port_1668873 | SOURCEANDSINK
Port_1670263 | SOURCEANDSINK
Port_1670413 | SOURCEANDSINK
Port_1670531 | SOURCEANDSINK
Port_1670641 | SOURCEANDSINK

# IfcDoor: Door_1:2'-0" X 8'-0", Door_1:2'-0" X 8'-0":1488988
In: First floor
Type - OperationType: SINGLE_SWING_RIGHT; ParameterTakesPrecedence: no; Sizeable: no; Material: Default New Material (2)
Type - Door_1:2'-0" X 8'-0":1488988 - PanelOperation: SWINGING
Type - Pset_DoorCommon - IsExternal: no; Reference: 2'-0" X 8'-0"
Type - Pset_ProductRequirements - Category: Doors
Type - Pset_QuantityTakeOff - Reference: 2'-0" X 8'-0"
OverallHeight: 8 ft; OverallWidth: 2 ft; Material: Default New Material
Pset_OpeningElementCommon - Reference: 2'-0" X 8'-0"; sets with these values: 2

# IfcDoor: Door_1:2'-4" X 8'-0" (4)
In: First floor
Type - OperationType: SINGLE_SWING_LEFT; ParameterTakesPrecedence: no; Sizeable: no; Material: Default New Material (2)
Type - Door_1:2'-4" X 8'-0":1463781 - PanelOperation: SWINGING
Type - Pset_DoorCommon - IsExternal: no; Reference: 2'-4" X 8'-0"
Type - Pset_ProductRequirements - Category: Doors
Type - Pset_QuantityTakeOff - Reference: 2'-4" X 8'-0"
OverallHeight: 8 ft; OverallWidth: 2.33333 ft; Material: Default New Material
Name (Door_1:2'-4" X 8'-0":...)
1463781
1463846
1484999
1485000

# IfcDoor: Door_1:2'-4" X 8'-0", Door_1:2'-4" X 8'-0":1472088
In: First floor
Type - OperationType: SINGLE_SWING_LEFT; ParameterTakesPrecedence: no; Sizeable: no; Material: Default New Material (2)
Type - Door_1:2'-4" X 8'-0":1472088 - PanelOperation: SWINGING
Type - Pset_DoorCommon - IsExternal: no; Reference: 2'-4" X 8'-0"
Type - Pset_ProductRequirements - Category: Doors
Type - Pset_QuantityTakeOff - Reference: 2'-4" X 8'-0"
OverallHeight: 8 ft; OverallWidth: 2.33333 ft; Material: Default New Material

# IfcDoor: Door_1:2'-4" X 8'-2" (3)
In: First floor
Type - OperationType: SINGLE_SWING_LEFT; ParameterTakesPrecedence: no; Sizeable: no; Material: Default New Material (2)
Type - Door_1:2'-4" X 8'-2":1468469 - PanelOperation: SWINGING
Type - Pset_DoorCommon - IsExternal: no; Reference: 2'-4" X 8'-2"
Type - Pset_ProductRequirements - Category: Doors
Type - Pset_QuantityTakeOff - Reference: 2'-4" X 8'-2"
OverallHeight: 8.16667 ft; OverallWidth: 2.33333 ft; Material: Default New Material
Name (Door_1:2'-4" X 8'-2":...)
1468469
1468739
1468795

# IfcDoor: Door_1:2'-4" X 8'-2", Door_1:2'-4" X 8'-2":1468661
In: First floor
Type - OperationType: SINGLE_SWING_RIGHT; ParameterTakesPrecedence: no; Sizeable: no; Material: Default New Material (2)
Type - Door_1:2'-4" X 8'-2":1468661 - PanelOperation: SWINGING
Type - Pset_DoorCommon - IsExternal: no; Reference: 2'-4" X 8'-2"
Type - Pset_ProductRequirements - Category: Doors
Type - Pset_QuantityTakeOff - Reference: 2'-4" X 8'-2"
OverallHeight: 8.16667 ft; OverallWidth: 2.33333 ft; Material: Default New Material

# IfcDoor: Door_1:2'-6" X 6'-8", Door_1:2'-6" X 6'-8":1467211
In: First floor
Type - OperationType: SINGLE_SWING_RIGHT; ParameterTakesPrecedence: no; Sizeable: no; Material: Default New Material (2)
Type - Door_1:2'-6" X 6'-8":1467211 - PanelOperation: SWINGING
Type - Pset_DoorCommon - IsExternal: no; Reference: 2'-6" X 6'-8"
Type - Pset_ProductRequirements - Category: Doors
Type - Pset_QuantityTakeOff - Reference: 2'-6" X 6'-8"
OverallHeight: 6.66667 ft; OverallWidth: 2.5 ft; Material: Default New Material

# IfcDoor: Door_1:2'-6" X 8'-0" (2)
In: First floor
Type - OperationType: SINGLE_SWING_RIGHT; ParameterTakesPrecedence: no; Sizeable: no; Material: Default New Material (2)
Type - Door_1:2'-6" X 8'-0":1460744 - PanelOperation: SWINGING
Type - Pset_DoorCommon - IsExternal: no; Reference: 2'-6" X 8'-0"
Type - Pset_ProductRequirements - Category: Doors
Type - Pset_QuantityTakeOff - Reference: 2'-6" X 8'-0"
OverallHeight: 8 ft; OverallWidth: 2.5 ft; Material: Default New Material
Name (Door_1:2'-6" X 8'-0":...)
1460744
1467514

# IfcDoor: Door_1:2'-6" X 8'-0", Door_1:2'-6" X 8'-0":1463663
In: First floor
Type - OperationType: SINGLE_SWING_RIGHT; ParameterTakesPrecedence: no; Sizeable: no; Material: Default New Material (2)
Type - Door_1:2'-6" X 8'-0":1463663 - PanelOperation: SWINGING
Type - Pset_DoorCommon - IsExternal: no; Reference: 2'-6" X 8'-0"
Type - Pset_ProductRequirements - Category: Doors
Type - Pset_QuantityTakeOff - Reference: 2'-6" X 8'-0"
OverallHeight: 8 ft; OverallWidth: 2.5 ft; Material: Default New Material

# IfcDoor: Door_1:2'-6" X 8'-0", Door_1:2'-6" X 8'-0":1470221
In: First floor
Type - OperationType: SINGLE_SWING_RIGHT; ParameterTakesPrecedence: no; Sizeable: no; Material: Default New Material (2)
Type - Door_1:2'-6" X 8'-0":1470221 - PanelOperation: SWINGING
Type - Pset_DoorCommon - IsExternal: no; Reference: 2'-6" X 8'-0"
Type - Pset_ProductRequirements - Category: Doors
Type - Pset_QuantityTakeOff - Reference: 2'-6" X 8'-0"
OverallHeight: 8 ft; OverallWidth: 2.5 ft; Material: Default New Material

# IfcDoor: Door_1:2'-6" X 8'-2", Door_1:2'-6" X 8'-2":1468600
In: First floor
Type - OperationType: SINGLE_SWING_LEFT; ParameterTakesPrecedence: no; Sizeable: no; Material: Default New Material (2)
Type - Door_1:2'-6" X 8'-2":1468600 - PanelOperation: SWINGING
Type - Pset_DoorCommon - IsExternal: no; Reference: 2'-6" X 8'-2"
Type - Pset_ProductRequirements - Category: Doors
Type - Pset_QuantityTakeOff - Reference: 2'-6" X 8'-2"
OverallHeight: 8.16667 ft; OverallWidth: 2.5 ft; Material: Default New Material

# IfcDoor: Door_1:2'-6" X 8'-2", Door_1:2'-6" X 8'-2":1469136
In: First floor
Type - OperationType: SINGLE_SWING_LEFT; ParameterTakesPrecedence: no; Sizeable: no; Material: Default New Material (2)
Type - Door_1:2'-6" X 8'-2":1469136 - PanelOperation: SWINGING
Type - Pset_DoorCommon - IsExternal: no; Reference: 2'-6" X 8'-2"
Type - Pset_ProductRequirements - Category: Doors
Type - Pset_QuantityTakeOff - Reference: 2'-6" X 8'-2"
OverallHeight: 8.16667 ft; OverallWidth: 2.5 ft; Material: Default New Material

# IfcDoor: Door_1:2'-8" X 8'-0", Door_1:2'-8" X 8'-0":1460842
In: First floor
Type - OperationType: SINGLE_SWING_LEFT; ParameterTakesPrecedence: no; Sizeable: no; Material: Default New Material (2)
Type - Door_1:2'-8" X 8'-0":1460842 - PanelOperation: SWINGING
Type - Pset_DoorCommon - IsExternal: no; Reference: 2'-8" X 8'-0"
Type - Pset_ProductRequirements - Category: Doors
Type - Pset_QuantityTakeOff - Reference: 2'-8" X 8'-0"
OverallHeight: 8 ft; OverallWidth: 2.66667 ft; Material: Default New Material

# IfcDoor: Door_1:3'-0" X 8'-0", Door_1:3'-0" X 8'-0":1485023
In: First floor
Type - OperationType: SINGLE_SWING_LEFT; ParameterTakesPrecedence: no; Sizeable: no; Material: Default New Material (2)
Type - Door_1:3'-0" X 8'-0":1485023 - PanelOperation: SWINGING
Type - Pset_DoorCommon - IsExternal: no; Reference: 3'-0" X 8'-0"
Type - Pset_ProductRequirements - Category: Doors
Type - Pset_QuantityTakeOff - Reference: 3'-0" X 8'-0"
OverallHeight: 8 ft; OverallWidth: 3 ft; Material: Default New Material

# IfcDoor: Door_1:3'-0" X 8'-0" (3)
In: First floor
Type - OperationType: SINGLE_SWING_RIGHT; ParameterTakesPrecedence: no; Sizeable: no; Material: Default New Material (2)
Type - Door_1:3'-0" X 8'-0":1461107 - PanelOperation: SWINGING
Type - Pset_DoorCommon - IsExternal: no; Reference: 3'-0" X 8'-0"
Type - Pset_ProductRequirements - Category: Doors
Type - Pset_QuantityTakeOff - Reference: 3'-0" X 8'-0"
OverallHeight: 8 ft; OverallWidth: 3 ft; Material: Default New Material
Name (Door_1:3'-0" X 8'-0":...)
1461107
1467320
1472085

# IfcDoor: Door_2:3'-0" X 8'-0", Door_2:3'-0" X 8'-0":1472081
In: First floor
Type - OperationType: SINGLE_SWING_LEFT; ParameterTakesPrecedence: no; Sizeable: no; Classification: B2030100 Glazed Doors & Entrances (Uniformat); Material: Default New Material (2), Glass
Type - Door_2:3'-0" X 8'-0":1472081 - LiningOffset: 0.0416667 ft; PanelOperation: SWINGING
Type - Pset_DoorCommon - IsExternal: no; Reference: 3'-0" X 8'-0"
Type - Pset_ProductRequirements - Category: Doors
Type - Pset_QuantityTakeOff - Reference: 3'-0" X 8'-0"
OverallHeight: 8 ft; OverallWidth: 3 ft; Material: Glass, Default New Material
Pset_DoorCommon - IsExternal: yes

# IfcDoor: Door_3:9'-4" X 7'-10", Door_3:9'-4" X 7'-10":1657547
In: First floor
Type - ParameterTakesPrecedence: no; Sizeable: no; Classification: C1020 Interior Doors (Uniformat); Material: Default New Material (2), Glass
Type - Pset_DoorCommon - IsExternal: no; Reference: 9'-4" X 7'-10"; ThermalTransmittance: 3.12872 kg/K/s3
Type - Pset_ProductRequirements - Category: Doors
Type - Pset_QuantityTakeOff - Reference: 9'-4" X 7'-10"
OverallHeight: 7.83333 ft; OverallWidth: 9.33333 ft; Material: Default New Material, Glass

# IfcDoor: Door_4:4'-8" X 8'-2", Door_4:4'-8" X 8'-2":1465125
In: First floor
Type - OperationType: DOUBLE_DOOR_SINGLE_SWING_OPPOSITE_LEFT; ParameterTakesPrecedence: no; Sizeable: no; Classification: C1020 Interior Doors (Uniformat); Material: Glass, Default New Material (2)
Type - Door_4:4'-8" X 8'-2":1465125 - PanelOperation: SWINGING
Type - Pset_DoorCommon - IsExternal: no; Reference: 4'-8" X 8'-2"; ThermalTransmittance: 3.12872 kg/K/s3
Type - Pset_ProductRequirements - Category: Doors
Type - Pset_QuantityTakeOff - Reference: 4'-8" X 8'-2"
OverallHeight: 8.16667 ft; OverallWidth: 4.66667 ft; Material: Glass, Default New Material

# IfcDoor: Door_5:4'-8" X 8'-0", Door_5:4'-8" X 8'-0":1483213
In: First floor
Type - OperationType: DOUBLE_DOOR_SINGLE_SWING_OPPOSITE_LEFT; ParameterTakesPrecedence: no; Sizeable: no; Classification: C1020 Interior Doors (Uniformat); Material: Default New Material (2), Glass
Type - Door_5:4'-8" X 8'-0":1483213 - PanelOperation: SWINGING
Type - Pset_DoorCommon - IsExternal: no; Reference: 4'-8" X 8'-0"; ThermalTransmittance: 3.12872 kg/K/s3
Type - Pset_ProductRequirements - Category: Doors
Type - Pset_QuantityTakeOff - Reference: 4'-8" X 8'-0"
OverallHeight: 8 ft; OverallWidth: 4.66667 ft; Material: Glass, Default New Material
Pset_OpeningElementCommon - Reference: 4'-8" X 8'-0"; sets with these values: 2

# IfcDoor: Door_6:3'-0" X 8'-0", Door_6:3'-0" X 8'-0":1483209
In: First floor
Type - OperationType: SINGLE_SWING_LEFT; ParameterTakesPrecedence: no; Sizeable: no; Classification: B2030100 Glazed Doors & Entrances (Uniformat); Material: Default New Material (2), Glass
Type - Door_6:3'-0" X 8'-0":1483209 - LiningOffset: 0.0416667 ft; PanelOperation: SWINGING
Type - Pset_DoorCommon - IsExternal: no; Reference: 3'-0" X 8'-0"
Type - Pset_ProductRequirements - Category: Doors
Type - Pset_QuantityTakeOff - Reference: 3'-0" X 8'-0"
OverallHeight: 8 ft; OverallWidth: 3 ft; Material: Glass, Default New Material
Pset_DoorCommon - IsExternal: yes

# IfcDoor: Door_7:4'-10" X 8'-0", Door_7:4'-10" X 8'-0":1469219
In: First floor
Type - ParameterTakesPrecedence: no; Sizeable: no; Classification: C1020 Interior Doors (Uniformat); Material: Default New Material (2)
Type - Pset_DoorCommon - IsExternal: no; Reference: 4'-10" X 8'-0"; ThermalTransmittance: 3.12872 kg/K/s3
Type - Pset_ProductRequirements - Category: Doors
Type - Pset_QuantityTakeOff - Reference: 4'-10" X 8'-0"
OverallHeight: 8 ft; OverallWidth: 4.83333 ft; Material: Default New Material

# IfcDoor: Door_8:5'-10" X 7'-8", Door_8:5'-10" X 7'-8":1488884
In: First floor
Type - ParameterTakesPrecedence: no; Sizeable: no; Classification: C1020 Interior Doors (Uniformat); Material: Default New Material (2)
Type - Pset_DoorCommon - IsExternal: no; Reference: 5'-10" X 7'-8"; ThermalTransmittance: 3.12872 kg/K/s3
Type - Pset_ProductRequirements - Category: Doors
Type - Pset_QuantityTakeOff - Reference: 5'-10" X 7'-8"
OverallHeight: 7.66667 ft; OverallWidth: 5.83333 ft; Material: Default New Material, Glass

# IfcFlowTerminal: Lighting Fixture He-Williams At1 1x4-Recessed:Light 5, Lighting Fixture He-Williams At1 1x4-Recessed:Light 5:1575098
In: First floor
Type - Material: Default New Material, Glass - HE-Williams - Frosted-Matte-Acrylic
Type - Pset_DistributionFlowElementCommon - Reference: Light 5
Type - Pset_ElectricalDeviceCommon - NumberOfPoles: 1
Type - Pset_ManufacturerTypeInformation - Manufacturer: H.E. Williams
Type - Pset_ProductRequirements - Category: Lighting Fixtures
Type - Pset_QuantityTakeOff - Reference: Light 5
Pset_DistributionFlowElementCommon - sets with these values: 2

# IfcFlowTerminal: Lighting_Fixtures_Ceiling_Linear:Light 11, Lighting_Fixtures_Ceiling_Linear:Light 11:1648893
In: First floor
Type - Material: Default New Material (2)
Type - Pset_DistributionFlowElementCommon - Reference: Light 11
Type - Pset_ProductRequirements - Category: Lighting Fixtures
Type - Pset_QuantityTakeOff - Reference: Light 11
Material: Default New Material
Pset_DistributionFlowElementCommon - sets with these values: 2

# IfcFlowTerminal: Lighting_Fixtures_Pendant_1:Light 4, Lighting_Fixtures_Pendant_1:Light 4:1550656
In: First floor
Type - Material: Glass - Frosted, Default New Material
Type - Pset_DistributionFlowElementCommon - Reference: Light 4
Type - Pset_ProductRequirements - Category: Lighting Fixtures
Type - Pset_QuantityTakeOff - Reference: Light 4
Material: Default New Material, Glass - Frosted
Pset_DistributionFlowElementCommon - sets with these values: 2

# IfcFlowTerminal: Lighting_Fixtures_Pendant_Lamp_Art Glass_LED:Light 7 (2)
In: First floor
Type - Material: Glass, Frosted, Default New Material
Type - Pset_DistributionFlowElementCommon - Reference: Light 7
Type - Pset_ElectricalDeviceCommon - NumberOfPoles: 1
Type - Pset_ProductRequirements - Category: Lighting Fixtures
Type - Pset_QuantityTakeOff - Reference: Light 7
Pset_DistributionFlowElementCommon - sets with these values: 2
Name (Lighting_Fixtures_Pendant_Lamp_Art Glass_LED:Light 7:...)
1559209
1635850

# IfcFlowTerminal: Lighting_Fixtures_Pendant_Lamp_Art Glass_LED:Light 8 (2)
In: First floor
Type - Material: Default New Material, Glass, Frosted
Type - Pset_DistributionFlowElementCommon - Reference: Light 8
Type - Pset_ElectricalDeviceCommon - NumberOfPoles: 1
Type - Pset_ProductRequirements - Category: Lighting Fixtures
Type - Pset_QuantityTakeOff - Reference: Light 8
Material: Glass, Frosted, Default New Material
Pset_DistributionFlowElementCommon - sets with these values: 2
Name (Lighting_Fixtures_Pendant_Lamp_Art Glass_LED:Light 8:...)
1561095
1654337

# IfcFlowTerminal: Lighting_Fixtures_Pendant_Lamp_Art Glass_LED:Light 9 (4)
In: First floor
Type - Material: Glass, Frosted, Default New Material
Type - Pset_DistributionFlowElementCommon - Reference: Light 9
Type - Pset_ElectricalDeviceCommon - NumberOfPoles: 1
Type - Pset_ProductRequirements - Category: Lighting Fixtures
Type - Pset_QuantityTakeOff - Reference: Light 9
Pset_DistributionFlowElementCommon - sets with these values: 2
Name (Lighting_Fixtures_Pendant_Lamp_Art Glass_LED:Light 9:...)
1593979
1594397
1594443
1594473

# IfcFlowTerminal: Lighting_Fixtures_Sconce_Lamp_Cosmetic_LED1:Light 8 (2)
In: First floor
Type - Material: Default New Material, Glass, White, High Luminance
Type - Pset_DistributionFlowElementCommon - Reference: Light 8
Type - Pset_ElectricalDeviceCommon - NumberOfPoles: 1
Type - Pset_ProductRequirements - Category: Lighting Fixtures
Type - Pset_QuantityTakeOff - Reference: Light 8
Material: Glass, White, High Luminance, Default New Material
Pset_DistributionFlowElementCommon - sets with these values: 2
Name (Lighting_Fixtures_Sconce_Lamp_Cosmetic_LED1:Light 8:...)
1647569
1647618

# IfcFlowTerminal: Lighting_Fixtures_Sconce_Lamp_Cosmetic_LED:Light 8, Lighting_Fixtures_Sconce_Lamp_Cosmetic_LED:Light 8:1563279
In: First floor
Type - Material: Glass, White, High Luminance, Default New Material
Type - Pset_DistributionFlowElementCommon - Reference: Light 8
Type - Pset_ElectricalDeviceCommon - NumberOfPoles: 1
Type - Pset_ProductRequirements - Category: Lighting Fixtures
Type - Pset_QuantityTakeOff - Reference: Light 8
Pset_DistributionFlowElementCommon - sets with these values: 2

# IfcFlowTerminal: M_Recessed Lamp - Round - LED:Light 2 (51)
In: First floor
Type - Material: Default New Material, Glass, White, High Luminance
Type - Pset_DistributionFlowElementCommon - Reference: Light 2
Type - Pset_ElectricalDeviceCommon - NumberOfPoles: 1
Type - Pset_ProductRequirements - Category: Lighting Fixtures
Type - Pset_QuantityTakeOff - Reference: Light 2
Pset_DistributionFlowElementCommon - sets with these values: 2
Name (M_Recessed Lamp - Round - LED:Light 2:...)
1505726
1505889
1505928
1505938
1506017
1506018
1506019
1506020
1521985
1522158
1522220
1522267
1522268
1522298
1522343
1522373
1522422
1522477
1522552
1522629
1522698
1522757
1522875
1522915
1522916
1522943
1551746
1551825
1552003
1575069
1575128
1575129
1575130
1643636
1643797
1666624
1666771
1668183
1668241
1668289
1668351
1668442
1668620
1668669
1668714
1668768
1668873
1670263
1670413
1670531
1670641

# IfcFlowTerminal: M_Wall Lamp - Bracket:Wall Light 1, M_Wall Lamp - Bracket:Wall Light 1:1536648
In: First floor
Type - Classification: D5020220 Lighting - Incandescent (Uniformat); Material: Glass, Frosted, Glass, White, High Luminance, Default New Material
Type - Pset_DistributionFlowElementCommon - Reference: Wall Light 1
Type - Pset_ProductRequirements - Category: Lighting Fixtures
Type - Pset_QuantityTakeOff - Reference: Wall Light 1
Material: Default New Material, Glass, White, High Luminance, Glass, Frosted
Pset_DistributionFlowElementCommon - sets with these values: 2

# IfcFlowTerminal: PIPES T L:Light 11 (4)
In: First floor
Type - Material: Default New Material (3), Intra lighting - White
Type - Pset_DistributionFlowElementCommon - Reference: Light 11
Type - Pset_ManufacturerTypeInformation - Manufacturer: Intra lighting
Type - Pset_ProductRequirements - Category: Lighting Fixtures
Type - Pset_QuantityTakeOff - Reference: Light 11
Material: Default New Material
Pset_DistributionFlowElementCommon - sets with these values: 2
Name (PIPES T L:Light 11:...)
1525877
1531003
1608332
1608445

# IfcFlowTerminal: PIPES T L:Light 11 (2)
In: First floor
Type - Material: Intra lighting - White, Default New Material (3)
Type - Pset_DistributionFlowElementCommon - Reference: Light 11
Type - Pset_ManufacturerTypeInformation - Manufacturer: Intra lighting
Type - Pset_ProductRequirements - Category: Lighting Fixtures
Type - Pset_QuantityTakeOff - Reference: Light 11
Material: Default New Material
Pset_DistributionFlowElementCommon - sets with these values: 2
Name (PIPES T L:Light 11:...)
1608591
1608735

# IfcFlowTerminal: Plumbing Fixtures 1:Plumbing Fixtures 1, Plumbing Fixtures 1:Plumbing Fixtures 1:1478820
In: First floor
Type - Material: Default New Material
Type - Pset_ProductRequirements - Category: Plumbing Fixtures
Type - Pset_QuantityTakeOff - Reference: Plumbing Fixtures 1
Pset_DistributionFlowElementCommon - Reference: Plumbing Fixtures 1; sets with these values: 3
Pset_ProductRequirements - sets with these values: 2

# IfcFlowTerminal: Plumbing Fixtures 2:Plumbing Fixtures 2, Plumbing Fixtures 2:Plumbing Fixtures 2:1506087
In: First floor
Type - Material: Default New Material
Type - Pset_ProductRequirements - Category: Plumbing Fixtures
Type - Pset_QuantityTakeOff - Reference: Plumbing Fixtures 2
Pset_DistributionFlowElementCommon - Reference: Plumbing Fixtures 2; sets with these values: 3
Pset_ProductRequirements - sets with these values: 2

# IfcFlowTerminal: Plumbing Fixtures 3:Plumbing Fixtures 3, Plumbing Fixtures 3:Plumbing Fixtures 3:1506110
In: First floor
Type - Material: Default New Material
Type - Pset_ProductRequirements - Category: Plumbing Fixtures
Type - Pset_QuantityTakeOff - Reference: Plumbing Fixtures 3
Pset_DistributionFlowElementCommon - Reference: Plumbing Fixtures 3; sets with these values: 3
Pset_ProductRequirements - sets with these values: 2

# IfcFlowTerminal: Plumbing Fixtures 4:Plumbing Fixtures 4, Plumbing Fixtures 4:Plumbing Fixtures 4:1506620
In: First floor
Type - Material: Default New Material
Type - Pset_ProductRequirements - Category: Plumbing Fixtures
Type - Pset_QuantityTakeOff - Reference: Plumbing Fixtures 4
Pset_DistributionFlowElementCommon - Reference: Plumbing Fixtures 4; sets with these values: 3
Pset_ProductRequirements - sets with these values: 2

# IfcFlowTerminal: Plumbing Fixtures 5:Plumbing Fixtures 5, Plumbing Fixtures 5:Plumbing Fixtures 5:1514768
In: First floor
Type - Material: Default New Material
Type - Pset_ProductRequirements - Category: Plumbing Fixtures
Type - Pset_QuantityTakeOff - Reference: Plumbing Fixtures 5
Pset_DistributionFlowElementCommon - Reference: Plumbing Fixtures 5; sets with these values: 3
Pset_ProductRequirements - sets with these values: 2

# IfcFlowTerminal: Plumbing Fixtures 6:Plumbing Fixtures 5, Plumbing Fixtures 6:Plumbing Fixtures 5:1516737
In: First floor
Type - Material: Default New Material
Type - Pset_ProductRequirements - Category: Plumbing Fixtures
Type - Pset_QuantityTakeOff - Reference: Plumbing Fixtures 5
Pset_DistributionFlowElementCommon - Reference: Plumbing Fixtures 5; sets with these values: 3
Pset_ProductRequirements - sets with these values: 2

# IfcFlowTerminal: Plumbing Fixtures 7:Plumbing Fixtures 7, Plumbing Fixtures 7:Plumbing Fixtures 7:1566211
In: First floor
Type - Material: Default New Material
Type - Pset_ProductRequirements - Category: Plumbing Fixtures
Type - Pset_QuantityTakeOff - Reference: Plumbing Fixtures 7
Pset_DistributionFlowElementCommon - Reference: Plumbing Fixtures 7; sets with these values: 3
Pset_ProductRequirements - sets with these values: 2
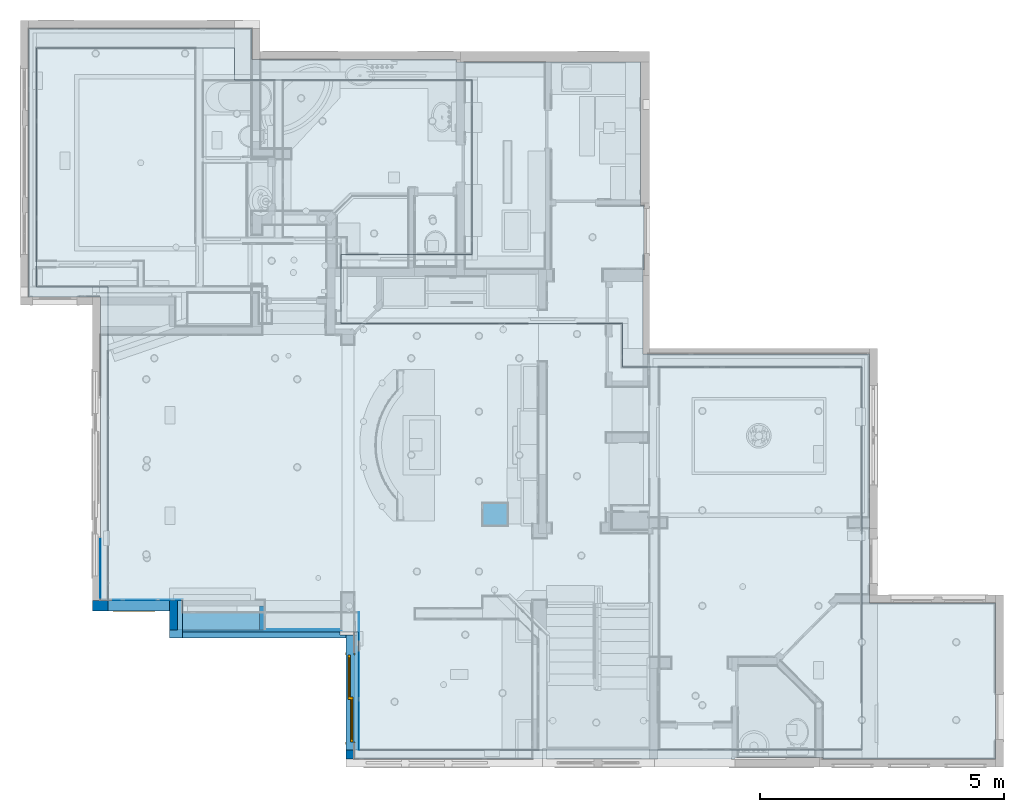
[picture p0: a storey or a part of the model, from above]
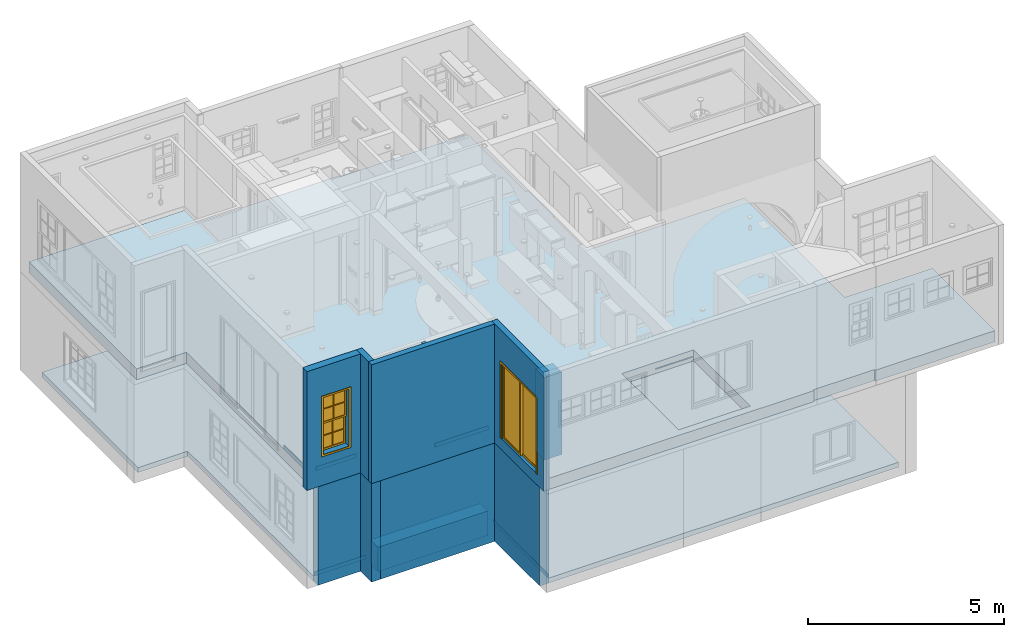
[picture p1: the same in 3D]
Properties of the parts of a building model (IFC2X3), part 2 of 2

# IfcFlowTerminal: Plumbing Fixtures 8:Plumbing Fixtures 8, Plumbing Fixtures 8:Plumbing Fixtures 8:1539070
In: First floor
Type - Material: Default New Material
Type - Pset_ProductRequirements - Category: Plumbing Fixtures
Type - Pset_QuantityTakeOff - Reference: Plumbing Fixtures 8
Pset_DistributionFlowElementCommon - Reference: Plumbing Fixtures 8; sets with these values: 3
Pset_ProductRequirements - sets with these values: 2

# IfcFlowTerminal: Water Closet - 1:Water Closet - 1 (3)
In: First floor
Type - Material: Default New Material (2)
Type - Pset_ProductRequirements - Category: Plumbing Fixtures
Type - Pset_QuantityTakeOff - Reference: Water Closet - 1
Material: Default New Material
Pset_DistributionFlowElementCommon - Reference: Water Closet - 1
Name (Water Closet - 1:Water Closet - 1:...) | Pset_DistributionFlowElementCommon, sets with these values | Pset_ProductRequirements, sets with these values
1476054 | 2
1513958 | 3 | 2
1513960 | 3 | 2

# IfcFurnishingElement: Casework 10:Casework 10, Casework 10:Casework 10:1547060
In: First floor
Type - Material: Default New Material
Type - Pset_ProductRequirements - Category: Casework
Type - Pset_QuantityTakeOff - Reference: Casework 10

# IfcFurnishingElement: Casework 11:Casework 11, Casework 11:Casework 11:1548229
In: First floor
Type - Material: Default New Material
Type - Pset_ProductRequirements - Category: Casework
Type - Pset_QuantityTakeOff - Reference: Casework 11
Material: Default New Material, Glass

# IfcFurnishingElement: Casework 12:Casework 12, Casework 12:Casework 12:1565270
In: First floor
Type - Material: Default New Material
Type - Pset_ProductRequirements - Category: Casework
Type - Pset_QuantityTakeOff - Reference: Casework 12

# IfcFurnishingElement: Casework 14:Casework 14, Casework 14:Casework 14:1568488
In: First floor
Type - Material: Default New Material
Type - Pset_ProductRequirements - Category: Casework
Type - Pset_QuantityTakeOff - Reference: Casework 14

# IfcFurnishingElement: Casework 15:Casework 15, Casework 15:Casework 15:1568782
In: First floor
Type - Material: Default New Material
Type - Pset_ProductRequirements - Category: Casework
Type - Pset_QuantityTakeOff - Reference: Casework 15

# IfcFurnishingElement: Casework 16:Casework 16, Casework 16:Casework 16:1569637
In: First floor
Type - Material: Default New Material
Type - Pset_ProductRequirements - Category: Casework
Type - Pset_QuantityTakeOff - Reference: Casework 16

# IfcFurnishingElement: Casework 18:Casework 18, Casework 18:Casework 18:1593246
In: First floor
Type - Material: Default New Material
Type - Pset_ProductRequirements - Category: Casework
Type - Pset_QuantityTakeOff - Reference: Casework 18

# IfcFurnishingElement: Casework 1:Casework 1, Casework 1:Casework 1:1476331
In: First floor
Type - Material: Default New Material
Type - Pset_ProductRequirements - Category: Casework
Type - Pset_QuantityTakeOff - Reference: Casework 1

# IfcFurnishingElement: Casework 2:Casework 2, Casework 2:Casework 2:1498048
In: First floor
Type - Material: Default New Material
Type - Pset_ProductRequirements - Category: Casework
Type - Pset_QuantityTakeOff - Reference: Casework 2

# IfcFurnishingElement: Casework 3:Casework 3, Casework 3:Casework 3:1506158
In: First floor
Type - Material: Default New Material
Type - Pset_ProductRequirements - Category: Casework
Type - Pset_QuantityTakeOff - Reference: Casework 3

# IfcFurnishingElement: Casework 5:Casework 3, Casework 5:Casework 3:1513130
In: First floor
Type - Material: Default New Material
Type - Pset_ProductRequirements - Category: Casework
Type - Pset_QuantityTakeOff - Reference: Casework 3

# IfcFurnishingElement: Casework 6:Casework 6, Casework 6:Casework 6:1516652
In: First floor
Type - Material: Default New Material
Type - Pset_ProductRequirements - Category: Casework
Type - Pset_QuantityTakeOff - Reference: Casework 6

# IfcFurnishingElement: Casework 7:Casework 7, Casework 7:Casework 7:1516764
In: First floor
Type - Material: Default New Material
Type - Pset_ProductRequirements - Category: Casework
Type - Pset_QuantityTakeOff - Reference: Casework 7

# IfcFurnishingElement: Casework 8:Casework 8, Casework 8:Casework 8:1517632
In: First floor
Type - Material: Default New Material
Type - Pset_ProductRequirements - Category: Casework
Type - Pset_QuantityTakeOff - Reference: Casework 8

# IfcFurnishingElement: Casework 9:Casework 9, Casework 9:Casework 9:1518422
In: First floor
Type - Material: Default New Material
Type - Pset_ProductRequirements - Category: Casework
Type - Pset_QuantityTakeOff - Reference: Casework 9

# IfcFurnishingElement: Casework_2:Casework_2 (9)
In: First floor
Type - Material: Default New Material
Type - Pset_ProductRequirements - Category: Casework
Type - Pset_QuantityTakeOff - Reference: Casework_2
Name (Casework_2:Casework_2:...)
1565271
1565279
1565281
1572392
1579953
1590435
1590436
1590438
1653800

# IfcFurnishingElement: Casework_4:Casework_4, Casework_4:Casework_4:1593231
In: First floor
Type - Material: Default New Material
Type - Pset_ProductRequirements - Category: Casework
Type - Pset_QuantityTakeOff - Reference: Casework_4
Material: Default New Material, Glass

# IfcFurnishingElement: Face Based Case work:2'-6" X 1'-7", Face Based Case work:2'-6" X 1'-7":1675897
In: First floor
Type - Material: Default New Material
Type - Pset_ProductRequirements - Category: Casework
Type - Pset_QuantityTakeOff - Reference: 2'-6" X 1'-7"

# IfcFurnishingElement: Generic Models 26:Generic Models 26, Generic Models 26:Generic Models 26:1568958
In: First floor
Type - Material: Default New Material
Type - Pset_ProductRequirements - Category: Casework
Type - Pset_QuantityTakeOff - Reference: Generic Models 26

# IfcFurnishingElement: Generic Models 27:Generic Models 26, Generic Models 27:Generic Models 26:1569100
In: First floor
Type - Material: Default New Material
Type - Pset_ProductRequirements - Category: Casework
Type - Pset_QuantityTakeOff - Reference: Generic Models 26

# IfcOpeningElement: Opening (73)
In: First floor
Name
Door_1:2'-6" X 8'-0":1463663:1
Basic Wall:Wall_7.5":1448645 | Classification: B2010 Exterior Walls (Uniformat); Pset_OpeningElementCommon - Reference: Wall void 1; sets with these values: 2; Pset_ProductRequirements - Category: Generic Models
Basic Wall:Wall_4.5":1449509 | Classification: B2010 Exterior Walls (Uniformat); Pset_OpeningElementCommon - Reference: Generic Models 22; sets with these values: 2; Pset_ProductRequirements - Category: Generic Models
Basic Wall:Wall_6.5":1449617 | Classification: B2010 Exterior Walls (Uniformat); Pset_OpeningElementCommon - Reference: Generic Models 16; sets with these values: 2; Pset_ProductRequirements - Category: Generic Models
Basic Wall:Wall_8":1449872 | Classification: B2010 Exterior Walls (Uniformat); Pset_OpeningElementCommon - Reference: Generic Models 58; sets with these values: 2; Pset_ProductRequirements - Category: Generic Models
Basic Wall:Wall_10":1450427 | Classification: B2010 Exterior Walls (Uniformat); Pset_OpeningElementCommon - Reference: Generic Models 45; sets with these values: 2; Pset_ProductRequirements - Category: Generic Models
Basic Wall:Wall_4.5":1450590 | Classification: B2010 Exterior Walls (Uniformat); Pset_OpeningElementCommon - Reference: 2'-0" X 8'-0"; sets with these values: 2; Pset_ProductRequirements - Category: Doors
Basic Wall:Wall_8.5":1452463 | Classification: B2010 Exterior Walls (Uniformat); Pset_OpeningElementCommon - Reference: Generic Models 44; sets with these values: 2; Pset_ProductRequirements - Category: Generic Models
Basic Wall:Wall_4.5":1452649 | Classification: B2010 Exterior Walls (Uniformat); Pset_OpeningElementCommon - Reference: Generic Models 13; sets with these values: 2; Pset_ProductRequirements - Category: Generic Models
Basic Wall:Wall_4.5":1452649 | Classification: B2010 Exterior Walls (Uniformat); Pset_OpeningElementCommon - Reference: Generic Models 17; sets with these values: 2; Pset_ProductRequirements - Category: Generic Models
Door_1:2'-8" X 8'-0":1460842:1
Basic Wall:Wall_4.5":1452738 | Classification: B2010 Exterior Walls (Uniformat); Pset_OpeningElementCommon - Reference: Generic Models 40; sets with these values: 2; Pset_ProductRequirements - Category: Generic Models
Basic Wall:Wall_4.5":1452738 | Classification: B2010 Exterior Walls (Uniformat); Pset_OpeningElementCommon - Reference: Generic Models 39; sets with these values: 2; Pset_ProductRequirements - Category: Generic Models
Basic Wall:Wall_8.5":1452879 | Classification: B2010 Exterior Walls (Uniformat); Pset_OpeningElementCommon - Reference: Generic Models 41; sets with these values: 2; Pset_ProductRequirements - Category: Generic Models
Basic Wall:Wall_4.5":1453299 | Classification: B2010 Exterior Walls (Uniformat); Pset_OpeningElementCommon - Reference: Generic Models 41; sets with these values: 2; Pset_ProductRequirements - Category: Generic Models
Basic Wall:Wall_6.75":1453414 | Classification: B2010 Exterior Walls (Uniformat); Pset_OpeningElementCommon - Reference: 4'-8" X 8'-0"; sets with these values: 2; Pset_ProductRequirements - Category: Doors
Basic Wall:Wall_9":1453939 | Classification: B2010 Exterior Walls (Uniformat); Pset_OpeningElementCommon - Reference: Generic Models 42; sets with these values: 2; Pset_ProductRequirements - Category: Generic Models
Basic Wall:Wall_4.5":1454139 | Classification: B2010 Exterior Walls (Uniformat); Pset_OpeningElementCommon - Reference: Generic Models 6; sets with these values: 2; Pset_ProductRequirements - Category: Generic Models
Basic Wall:Wall_4.5":1454142 | Classification: B2010 Exterior Walls (Uniformat); Pset_OpeningElementCommon - Reference: Generic Models 4; sets with these values: 2; Pset_ProductRequirements - Category: Generic Models
Basic Wall:Wall_10":1454146 | Classification: B2010 Exterior Walls (Uniformat); Pset_OpeningElementCommon - Reference: Generic Models 46; sets with these values: 2; Pset_ProductRequirements - Category: Generic Models
Floor:Floor_13.5":1456914:2 | Classification: B1010 Floor Construction (Uniformat); Pset_OpeningElementCommon - Reference: Floor_13.5"; sets with these values: 2; Pset_ProductRequirements - Category: Floors; Pset_ElementShading - Roughness: 3 ft
Window_8:2'-6" X 2'-6":1481301:1
Window_8:2'-6" X 2'-6":1472989:1
Window_13:6'-8" X 5'-10":1472092:1
Door_7:4'-10" X 8'-0":1469219:1
Door_1:2'-4" X 8'-2":1468795:1
Door_1:2'-6" X 8'-2":1469136:1
Basic Wall:Wall Border_T1:1588962 | Classification: B2010 Exterior Walls (Uniformat); Pset_OpeningElementCommon - Reference: 2'-0" X 8'-0"; sets with these values: 2; Pset_ProductRequirements - Category: Doors
Door_1:2'-4" X 8'-2":1468739:1
Door_1:2'-6" X 8'-2":1468600:1
Door_1:2'-6" X 8'-0":1467514:1
Door_1:3'-0" X 8'-0":1467320:1
Door_1:2'-4" X 8'-2":1468469:1
Basic Wall:Wall_6.5":1676951 | Classification: B2010 Exterior Walls (Uniformat); Pset_OpeningElementCommon - Reference: Generic Models 63; sets with these values: 2; Pset_ProductRequirements - Category: Generic Models
Door_1:2'-4" X 8'-2":1468661:1
Door_1:3'-0" X 8'-0":1485023:1
Window_5:2'-6" X 2'-6":1635432:1
Window_5:2'-6" X 2'-6":1633320:1
Window_5:2'-6" X 2'-6":1635560:1
Window_4:1'-10" X 3'-10":1485012:1
Window_9:5'-6" X 4'-8":1487284:1
Window_10:8'-2" X 2'-4":1487686:1
Door_8:5'-10" X 7'-8":1488884:1
Window_4:2'-6" X 5'-10":1489094:1
Door_3:9'-4" X 7'-10":1657547:1
Door_2:3'-0" X 8'-0":1472081:1
Window_3:12'-6" X 5'-10":1472062:1
Window_4:2'-0" X 3'-10":1471126:1
Window_4:2'-0" X 3'-10":1471128:1
Window_4:2'-0" X 3'-10":1470228:1
Window_2:4'-8" X 3'-10":1471122:1
Window_4:2'-4" X 3'-10":1460397:1
Door_1:3'-0" X 8'-0":1461107:1
Window_11:6'-4" X 5'-8":1486150:1
Door_6:3'-0" X 8'-0":1483209:1
Door_1:2'-6" X 8'-0":1470221:1
Door_1:2'-0" X 8'-0":1488988:1
Door_1:3'-0" X 8'-0":1472085:1
Door_1:2'-4" X 8'-0":1472088:1
Door_1:2'-6" X 8'-0":1460744:1
Door_1:2'-4" X 8'-0":1463781:1
Door_1:2'-4" X 8'-0":1463846:1
Door_5:4'-8" X 8'-0":1483213:1
Door_1:2'-4" X 8'-0":1485000:1
Door_1:2'-4" X 8'-0":1484999:1
Door_1:2'-6" X 6'-8":1467211:1
Window_6:3'-8" X 3'-8":1461024:1
Door_4:4'-8" X 8'-2":1465125:1
Window_4:2'-10" X 4'-10":1467646:1
Window_1:5'-10" X 4'-10":1467811:1
Window_4:2'-10" X 4'-10":1468012:1
Window_7:5'-0" X 4'-8":1469384:1
Window_6:3'-10" X 4'-0":1468910:1

# IfcOpeningElement: Recess (8)
In: First floor
Name | Classification | Reference | sets with these values | Category
Basic Wall:Wall_6.5":1447216 | B2010 Exterior Walls (Uniformat) | Generic Models 48 | 2 | Generic Models
Basic Wall:Wall_6.5":1447216 | B2010 Exterior Walls (Uniformat) | Generic Models 50 | 2 | Generic Models
Basic Wall:Wall_6.5":1447216 | B2010 Exterior Walls (Uniformat) | Generic Models 49 | 2 | Generic Models
Basic Wall:Wall_6.5":1449617 | B2010 Exterior Walls (Uniformat) | Generic Models 19 | 2 | Generic Models
Basic Wall:Wall_11":1449972 | B2010 Exterior Walls (Uniformat) | Generic Models 18 | 2 | Generic Models
Basic Wall:Wall_10":1450427 | B2010 Exterior Walls (Uniformat) | 2'-0" X 8'-0" | 2 | Doors
Basic Wall:Wall_4.5":1450590 | B2010 Exterior Walls (Uniformat) | Generic Models 62 | 2 | Generic Models


# IfcRailing: Railing:Railing_1.3 2 (3)
In: First floor
Classification: C2010400 Stair Handrails/Balustrades (Uniformat); Material: Default New Material
Pset_ProductRequirements - Category: Railings
Pset_QuantityTakeOff - Reference: Railing_1.3 2
Pset_RailingCommon - IsExternal: no; Reference: Railing_1.3 2; Height: 3 ft
Name (Railing:Railing_1.3 2:...)
1544968
1550134
1550346

# IfcRailing: Railing:Railing_1.3 3, Railing:Railing_1.3 3:1542665
In: First floor
Classification: C2010400 Stair Handrails/Balustrades (Uniformat); Material: Default New Material
Pset_ProductRequirements - Category: Railings
Pset_QuantityTakeOff - Reference: Railing_1.3 3
Pset_RailingCommon - IsExternal: no; Reference: Railing_1.3 3; Height: 3.16667 ft

# IfcRailing: Railing:Railing_4, Railing:Railing_4:1540970
In: First floor
Classification: C2010400 Stair Handrails/Balustrades (Uniformat); Material: Default New Material
Pset_ProductRequirements - Category: Railings
Pset_QuantityTakeOff - Reference: Railing_4
Pset_RailingCommon - IsExternal: no; Reference: Railing_4; Height: 3 ft

# IfcRailing: Railing:Railing_4 2 (2)
In: First floor
Classification: C2010400 Stair Handrails/Balustrades (Uniformat); Material: Default New Material
Pset_ProductRequirements - Category: Railings
Pset_QuantityTakeOff - Reference: Railing_4 2
Pset_RailingCommon - IsExternal: no; Reference: Railing_4 2; Height: 3.58333 ft
Name (Railing:Railing_4 2:...)
1540974
1542400

# IfcRailing: Railing:Railing_4 3, Railing:Railing_4 3:1545138
In: First floor
Classification: C2010400 Stair Handrails/Balustrades (Uniformat); Material: Default New Material
Pset_ProductRequirements - Category: Railings
Pset_QuantityTakeOff - Reference: Railing_4 3
Pset_RailingCommon - IsExternal: no; Reference: Railing_4 3; Height: 2.83333 ft

# IfcSlab: Floor:Floor_13.5", Floor:Floor_13.5":1456914
In: First floor
Type - PredefinedType: FLOOR; Material: Default New Material 1.125 ft
Type - Pset_ElementShading - Roughness: 3 ft
Type - Pset_ProductRequirements - Category: Floors
Type - Pset_QuantityTakeOff - Reference: Floor_13.5"
Type - Pset_ReinforcementBarPitchOfSlab - Reference: Floor_13.5"
Type - Pset_SlabCommon - IsExternal: no; Reference: Floor_13.5"
Classification: B1010 Floor Construction (Uniformat)
Pset_QuantityTakeOff - sets with these values: 2
Pset_SlabCommon - LoadBearing: no; PitchAngle: 0 deg

# IfcSlab: Floor:Floor_6", Floor:Floor_6":1456545
In: First floor
Type - PredefinedType: FLOOR; Material: Default New Material 0.5 ft
Type - Pset_ElementShading - Roughness: 3 ft
Type - Pset_ProductRequirements - Category: Floors
Type - Pset_QuantityTakeOff - Reference: Floor_6"
Type - Pset_ReinforcementBarPitchOfSlab - Reference: Floor_6"
Type - Pset_SlabCommon - IsExternal: no; Reference: Floor_6"
Classification: B1010 Floor Construction (Uniformat)
Pset_QuantityTakeOff - sets with these values: 2
Pset_SlabCommon - LoadBearing: no; PitchAngle: 0 deg

# IfcStair: Assembled Stair:Stair_2018, Assembled Stair:Stair:1540941
In: First floor
Classification: C Interiors (Uniformat)
Pset_ProductRequirements - Category: Stairs
Pset_QuantityTakeOff - Reference: Stair_2018
Pset_StairCommon - IsExternal: no; Reference: Stair_2018; NumberOfRiser: 16; NumberOfTreads: 16; RiserHeight: 0.627604 ft; TreadLength: 1 ft

# IfcStairFlight: Non-Monolithic Run:1" Tread 1" Nosing 1/4" Riser 2, Assembled Stair:Stair:1540941 Run 1
In: First floor
Type - Pset_ProductRequirements - Category: Runs
Type - Pset_QuantityTakeOff - Reference: 1" Tread 1" Nosing 1/4" Riser 2
Type - Pset_StairFlightCommon - Reference: 1" Tread 1" Nosing 1/4" Riser 2; NosingLength: 0.0833333 ft
NumberOfRiser: 16; NumberOfTreads: 16; RiserHeight: 0.627604 ft; TreadLength: 1 ft; Classification: C Interiors (Uniformat); Material: Default New Material
Pset_StairFlightCommon - NumberOfRiser: 16; NumberOfTreads: 16; RiserHeight: 0.627604 ft; TreadLength: 1 ft; TreadLengthAtOffset: 1 ft; TreadLengthAtInnerSide: 1 ft

# IfcWall: Basic Wall:Wall_1'3", Basic Wall:Wall_1'3":1454116
In: First floor
Type - PredefinedType: STANDARD; Material: Default New Material 1.25 ft
Type - Pset_ElementShading - Roughness: 1 ft
Type - Pset_ProductRequirements - Category: Walls
Type - Pset_QuantityTakeOff - Reference: Wall_1'3"
Type - Pset_ReinforcementBarPitchOfWall - Reference: Wall_1'3"
Type - Pset_WallCommon - IsExternal: no; Reference: Wall_1'3"
Pset_QuantityTakeOff - sets with these values: 2
Pset_WallCommon - IsExternal: yes; ExtendToStructure: no; LoadBearing: no

# IfcWall: Basic Wall:Wall_11", Basic Wall:Wall_11":1452563
In: First floor
Type - PredefinedType: STANDARD; Material: Default New Material 0.916667 ft
Type - Pset_ElementShading - Roughness: 3 ft
Type - Pset_ProductRequirements - Category: Walls
Type - Pset_QuantityTakeOff - Reference: Wall_11"
Type - Pset_ReinforcementBarPitchOfWall - Reference: Wall_11"
Type - Pset_WallCommon - IsExternal: no; Reference: Wall_11"
Classification: B2010 Exterior Walls (Uniformat)
Pset_QuantityTakeOff - sets with these values: 2
Pset_WallCommon - IsExternal: yes; ExtendToStructure: no; LoadBearing: no

# IfcWall: Basic Wall:Wall_4.5", Basic Wall:Wall_4.5":1452114
In: First floor
Type - PredefinedType: STANDARD; Material: Default New Material 0.375 ft
Type - Pset_ElementShading - Roughness: 3 ft
Type - Pset_ProductRequirements - Category: Walls
Type - Pset_QuantityTakeOff - Reference: Wall_4.5"
Type - Pset_ReinforcementBarPitchOfWall - Reference: Wall_4.5"
Type - Pset_WallCommon - IsExternal: no; Reference: Wall_4.5"
Classification: B2010 Exterior Walls (Uniformat)
Pset_QuantityTakeOff - sets with these values: 2
Pset_WallCommon - IsExternal: yes; ExtendToStructure: no; LoadBearing: no

# IfcWall: Basic Wall:Wall_6.5" (2)
In: First floor
Type - PredefinedType: STANDARD; Material: Default New Material 0.541667 ft
Type - Pset_ElementShading - Roughness: 3 ft
Type - Pset_ProductRequirements - Category: Walls
Type - Pset_QuantityTakeOff - Reference: Wall_6.5"
Type - Pset_ReinforcementBarPitchOfWall - Reference: Wall_6.5"
Type - Pset_WallCommon - Reference: Wall_6.5"; IsExternal: no
Classification: B2010 Exterior Walls (Uniformat)
Pset_QuantityTakeOff - sets with these values: 2
Pset_WallCommon - IsExternal: yes; ExtendToStructure: no; LoadBearing: no
Name (Basic Wall:Wall_6.5":...)
1451636
1452282

# IfcWall: Basic Wall:Wall_9.5", Basic Wall:Wall_9.5":1452233
In: First floor
Type - PredefinedType: STANDARD; Material: Default New Material 0.791667 ft
Type - Pset_ElementShading - Roughness: 3 ft
Type - Pset_ProductRequirements - Category: Walls
Type - Pset_QuantityTakeOff - Reference: Wall_9.5"
Type - Pset_ReinforcementBarPitchOfWall - Reference: Wall_9.5"
Type - Pset_WallCommon - IsExternal: no; Reference: Wall_9.5"
Classification: B2010 Exterior Walls (Uniformat); Material: Default New Material
Pset_QuantityTakeOff - sets with these values: 2
Pset_WallCommon - IsExternal: yes; ExtendToStructure: no; LoadBearing: no

# IfcWallStandardCase: Basic Wall:Wall Border_T1 (264)
In: First floor
Type - PredefinedType: STANDARD; Material: Default New Material 0.0416667 ft
Type - Pset_ElementShading - Roughness: 3 ft
Type - Pset_ProductRequirements - Category: Walls
Type - Pset_QuantityTakeOff - Reference: Wall Border_T1
Type - Pset_ReinforcementBarPitchOfWall - Reference: Wall Border_T1
Type - Pset_WallCommon - IsExternal: no; Reference: Wall Border_T1
Classification: B2010 Exterior Walls (Uniformat)
Pset_QuantityTakeOff - sets with these values: 2
Pset_WallCommon - IsExternal: yes; ExtendToStructure: no; LoadBearing: no
Name (Basic Wall:Wall Border_T1:...)
1473636
1473637
1473638
1473639
1473640
1473641
1473643
1473647
1473648
1473649
1473650
1473651
1473652
1473653
1473655
1473656
1473657
1473658
1473659
1473660
1473661
1473662
1473665
1473683
1473702
1473741
1473757
1473804
1473854
1473898
1473962
1473984
1474051
1474136
1474223
1474303
1474367
1475498
1475516
1475661
1475784
1478893
1478944
1478991
1479036
1479177
1479364
1479430
1479479
1479563
1479620
1479772
1479971
1480112
1480277
1480327
1480378
1480418
1480525
1480582
1480672
1480710
1480796
1480818
1480905
1481101
1485026
1485027
1485028
1485029
1485031
1485032
1485033
1506941
1532423
1532452
1532492
1532506
1532528
1532587
1532620
1532654
1532677
1532725
1532747
1532790
1533527
1533601
1533622
1533681
1533701
1534497
1534532
1534559
1538961
1539003
1539028
1551732
1551733
1551734
1551735
1551736
1551737
1551738
1551739
1552223
1552309
1552333
1552403
1552488
1552560
1552561
1552562
1552563
1552564
1552565
1552619
1552654
1552668
1552695
1552725
1552778
1552817
1552860
1552898
1552918
1552954
1556206
1559536
1559564
1559873
1559905
1559925
1560049
1560070
1560098
1560717
1560745
1561427
1561453
1561475
1566143
1566144
1566145
1568122
1568126
1568127
1568128
1568191
1568192
1568193
1568194
1568195
1568196
1568197
1568276
1568277
1568278
1568279
1568280
1568789
1568814
1568836
1568970
1568998
1569028
1569135
1580001
1580002
1580003
1580004
1580005
1580006
1580007
1580012
1580016
1580017
1580018
1580039
1580152
1580197
1580297
1580853
1580865
1581057
1581743
1581794
1581915
1582070
1582175
1582352
1582519
1582579
1582662
1582750
1582826
1582941
1583091
1583188
1583308
1583439
1583577
1583747
1583825
1583946
1584470
1585185
1585218
1585398
1585483
1585517
1585595
1585659
1585708
1585732
1585794
1585853
1585918
1586020
1586041
1586256
1586289
1587632
1587784
1587814
1587953
1588041
1588123
1588318
1588438
1588497
1588598
1588696
1588758
1588823
1588883
1588962
1589012
1589133
1589262
1589374
1589587
1590440
1590441
1590442
1593230
1593268
1593637
1593667
1593680
1593731
1593768
1593794
1593915
1603242
1609395
1609423
1609503
1616024
1623357
1632853
1647489
1648498
1686969

# IfcWallStandardCase: Basic Wall:Wall_1' 1 3/4", Basic Wall:Wall_1' 1 3/4":1454118
In: First floor
Type - PredefinedType: STANDARD; Material: Default New Material 1.14583 ft
Type - Pset_ElementShading - Roughness: 1 ft
Type - Pset_ProductRequirements - Category: Walls
Type - Pset_QuantityTakeOff - Reference: Wall_1' 1 3/4"
Type - Pset_ReinforcementBarPitchOfWall - Reference: Wall_1' 1 3/4"
Type - Pset_WallCommon - IsExternal: no; Reference: Wall_1' 1 3/4"
Pset_QuantityTakeOff - sets with these values: 2
Pset_WallCommon - IsExternal: yes; ExtendToStructure: no; LoadBearing: no

# IfcWallStandardCase: Basic Wall:Wall_1' 10", Basic Wall:Wall_1' 10":1454130
In: First floor
Type - PredefinedType: STANDARD; Material: Default New Material 1.83333 ft
Type - Pset_ElementShading - Roughness: 1 ft
Type - Pset_ProductRequirements - Category: Walls
Type - Pset_QuantityTakeOff - Reference: Wall_1' 10"
Type - Pset_ReinforcementBarPitchOfWall - Reference: Wall_1' 10"
Type - Pset_WallCommon - IsExternal: no; Reference: Wall_1' 10"
Pset_QuantityTakeOff - sets with these values: 2
Pset_WallCommon - IsExternal: yes; ExtendToStructure: no; LoadBearing: no

# IfcWallStandardCase: Basic Wall:Wall_1' 2 1/2", Basic Wall:Wall_1' 2 1/2":1454128
In: First floor
Type - PredefinedType: STANDARD; Material: Default New Material 1.20833 ft
Type - Pset_ElementShading - Roughness: 1 ft
Type - Pset_ProductRequirements - Category: Walls
Type - Pset_QuantityTakeOff - Reference: Wall_1' 2 1/2"
Type - Pset_ReinforcementBarPitchOfWall - Reference: Wall_1' 2 1/2"
Type - Pset_WallCommon - IsExternal: no; Reference: Wall_1' 2 1/2"
Pset_QuantityTakeOff - sets with these values: 2
Pset_WallCommon - IsExternal: yes; ExtendToStructure: no; LoadBearing: no

# IfcWallStandardCase: Basic Wall:Wall_1' 3 1/2", Basic Wall:Wall_1' 3 1/2":1454155
In: First floor
Type - PredefinedType: STANDARD; Material: Default New Material 1.29167 ft
Type - Pset_ElementShading - Roughness: 1 ft
Type - Pset_ProductRequirements - Category: Walls
Type - Pset_QuantityTakeOff - Reference: Wall_1' 3 1/2"
Type - Pset_ReinforcementBarPitchOfWall - Reference: Wall_1' 3 1/2"
Type - Pset_WallCommon - IsExternal: no; Reference: Wall_1' 3 1/2"
Pset_QuantityTakeOff - sets with these values: 2
Pset_WallCommon - IsExternal: yes; ExtendToStructure: no; LoadBearing: no

# IfcWallStandardCase: Basic Wall:Wall_1' 3/4", Basic Wall:Wall_1' 3/4":1454129
In: First floor
Type - PredefinedType: STANDARD; Material: Default New Material 1.0625 ft
Type - Pset_ElementShading - Roughness: 1 ft
Type - Pset_ProductRequirements - Category: Walls
Type - Pset_QuantityTakeOff - Reference: Wall_1' 3/4"
Type - Pset_ReinforcementBarPitchOfWall - Reference: Wall_1' 3/4"
Type - Pset_WallCommon - IsExternal: no; Reference: Wall_1' 3/4"
Pset_QuantityTakeOff - sets with these values: 2
Pset_WallCommon - IsExternal: yes; ExtendToStructure: no; LoadBearing: no

# IfcWallStandardCase: Basic Wall:Wall_1' 8 1/2", Basic Wall:Wall_1' 8 1/2":1454131
In: First floor
Type - PredefinedType: STANDARD; Material: Default New Material 1.70833 ft
Type - Pset_ElementShading - Roughness: 1 ft
Type - Pset_ProductRequirements - Category: Walls
Type - Pset_QuantityTakeOff - Reference: Wall_1' 8 1/2"
Type - Pset_ReinforcementBarPitchOfWall - Reference: Wall_1' 8 1/2"
Type - Pset_WallCommon - IsExternal: no; Reference: Wall_1' 8 1/2"
Pset_QuantityTakeOff - sets with these values: 2
Pset_WallCommon - IsExternal: yes; ExtendToStructure: no; LoadBearing: no

# IfcWallStandardCase: Basic Wall:Wall_1'1/2" (2)
In: First floor
Type - PredefinedType: STANDARD; Material: Default New Material 1.04167 ft
Type - Pset_ElementShading - Roughness: 1 ft
Type - Pset_ProductRequirements - Category: Walls
Type - Pset_QuantityTakeOff - Reference: Wall_1'1/2"
Type - Pset_ReinforcementBarPitchOfWall - Reference: Wall_1'1/2"
Type - Pset_WallCommon - IsExternal: no; Reference: Wall_1'1/2"
Pset_QuantityTakeOff - sets with these values: 2
Pset_WallCommon - IsExternal: yes; ExtendToStructure: no; LoadBearing: no
Name (Basic Wall:Wall_1'1/2":...)
1454113
1454127

# IfcWallStandardCase: Basic Wall:Wall_1'2", Basic Wall:Wall_1'2":1454115
In: First floor
Type - PredefinedType: STANDARD; Material: Default New Material 1.16667 ft
Type - Pset_ElementShading - Roughness: 1 ft
Type - Pset_ProductRequirements - Category: Walls
Type - Pset_QuantityTakeOff - Reference: Wall_1'2"
Type - Pset_ReinforcementBarPitchOfWall - Reference: Wall_1'2"
Type - Pset_WallCommon - IsExternal: no; Reference: Wall_1'2"
Pset_QuantityTakeOff - sets with these values: 2
Pset_WallCommon - IsExternal: yes; ExtendToStructure: no; LoadBearing: no

# IfcWallStandardCase: Basic Wall:Wall_1'3" (2)
In: First floor
Type - PredefinedType: STANDARD; Material: Default New Material 1.25 ft
Type - Pset_ElementShading - Roughness: 1 ft
Type - Pset_ProductRequirements - Category: Walls
Type - Pset_QuantityTakeOff - Reference: Wall_1'3"
Type - Pset_ReinforcementBarPitchOfWall - Reference: Wall_1'3"
Type - Pset_WallCommon - IsExternal: no; Reference: Wall_1'3"
Pset_QuantityTakeOff - sets with these values: 2
Pset_WallCommon - IsExternal: yes; ExtendToStructure: no; LoadBearing: no
Name (Basic Wall:Wall_1'3":...)
1454114
1454141

# IfcWallStandardCase: Basic Wall:Wall_1'6", Basic Wall:Wall_1'6":1454121
In: First floor
Type - PredefinedType: STANDARD; Material: Default New Material 1.5 ft
Type - Pset_ElementShading - Roughness: 3 ft
Type - Pset_ProductRequirements - Category: Walls
Type - Pset_QuantityTakeOff - Reference: Wall_1'6"
Type - Pset_ReinforcementBarPitchOfWall - Reference: Wall_1'6"
Type - Pset_WallCommon - IsExternal: no; Reference: Wall_1'6"
Classification: B2010 Exterior Walls (Uniformat)
Pset_QuantityTakeOff - sets with these values: 2
Pset_WallCommon - IsExternal: yes; ExtendToStructure: no; LoadBearing: no

# IfcWallStandardCase: Basic Wall:Wall_1'7", Basic Wall:Wall_1'7":1454140
In: First floor
Type - PredefinedType: STANDARD; Material: Default New Material 1.58333 ft
Type - Pset_ElementShading - Roughness: 1 ft
Type - Pset_ProductRequirements - Category: Walls
Type - Pset_QuantityTakeOff - Reference: Wall_1'7"
Type - Pset_ReinforcementBarPitchOfWall - Reference: Wall_1'7"
Type - Pset_WallCommon - IsExternal: no; Reference: Wall_1'7"
Pset_QuantityTakeOff - sets with these values: 2
Pset_WallCommon - IsExternal: yes; ExtendToStructure: no; LoadBearing: no

# IfcWallStandardCase: Basic Wall:Wall_10" (3)
In: First floor
Type - PredefinedType: STANDARD; Material: Default New Material 0.833333 ft
Type - Pset_ElementShading - Roughness: 3 ft
Type - Pset_ProductRequirements - Category: Walls
Type - Pset_QuantityTakeOff - Reference: Wall_10"
Type - Pset_ReinforcementBarPitchOfWall - Reference: Wall_10"
Type - Pset_WallCommon - IsExternal: no; Reference: Wall_10"
Classification: B2010 Exterior Walls (Uniformat)
Pset_QuantityTakeOff - sets with these values: 2
Pset_WallCommon - IsExternal: yes; ExtendToStructure: no; LoadBearing: no
Name (Basic Wall:Wall_10":...)
1450427
1454123
1454146

# IfcWallStandardCase: Basic Wall:Wall_10.5", Basic Wall:Wall_10.5":1454125
In: First floor
Type - PredefinedType: STANDARD; Material: Default New Material 0.875 ft
Type - Pset_ElementShading - Roughness: 3 ft
Type - Pset_ProductRequirements - Category: Walls
Type - Pset_QuantityTakeOff - Reference: Wall_10.5"
Type - Pset_ReinforcementBarPitchOfWall - Reference: Wall_10.5"
Type - Pset_WallCommon - IsExternal: no; Reference: Wall_10.5"
Classification: B2010 Exterior Walls (Uniformat)
Pset_QuantityTakeOff - sets with these values: 2
Pset_WallCommon - IsExternal: yes; ExtendToStructure: no; LoadBearing: no

# IfcWallStandardCase: Basic Wall:Wall_11", Basic Wall:Wall_11":1449972
In: First floor
Type - PredefinedType: STANDARD; Material: Default New Material 0.916667 ft
Type - Pset_ElementShading - Roughness: 3 ft
Type - Pset_ProductRequirements - Category: Walls
Type - Pset_QuantityTakeOff - Reference: Wall_11"
Type - Pset_ReinforcementBarPitchOfWall - Reference: Wall_11"
Type - Pset_WallCommon - IsExternal: no; Reference: Wall_11"
Classification: B2010 Exterior Walls (Uniformat)
Pset_QuantityTakeOff - sets with these values: 2
Pset_WallCommon - IsExternal: yes; ExtendToStructure: no; LoadBearing: no

# IfcWallStandardCase: Basic Wall:Wall_17", Basic Wall:Wall_17":1453230
In: First floor
Type - PredefinedType: STANDARD; Material: Default New Material 1.41667 ft
Type - Pset_ElementShading - Roughness: 3 ft
Type - Pset_ProductRequirements - Category: Walls
Type - Pset_QuantityTakeOff - Reference: Wall_17"
Type - Pset_ReinforcementBarPitchOfWall - Reference: Wall_17"
Type - Pset_WallCommon - IsExternal: no; Reference: Wall_17"
Classification: B2010 Exterior Walls (Uniformat)
Pset_QuantityTakeOff - sets with these values: 2
Pset_WallCommon - IsExternal: yes; ExtendToStructure: no; LoadBearing: no

# IfcWallStandardCase: Basic Wall:Wall_3.5", Basic Wall:Wall_3.5":1451945
In: First floor
Type - PredefinedType: STANDARD; Material: Default New Material 0.291667 ft
Type - Pset_ElementShading - Roughness: 3 ft
Type - Pset_ProductRequirements - Category: Walls
Type - Pset_QuantityTakeOff - Reference: Wall_3.5"
Type - Pset_ReinforcementBarPitchOfWall - Reference: Wall_3.5"
Type - Pset_WallCommon - IsExternal: no; Reference: Wall_3.5"
Classification: B2010 Exterior Walls (Uniformat)
Pset_QuantityTakeOff - sets with these values: 2
Pset_WallCommon - IsExternal: yes; ExtendToStructure: no; LoadBearing: no

# IfcWallStandardCase: Basic Wall:Wall_4.5" (37)
In: First floor
Type - PredefinedType: STANDARD; Material: Default New Material 0.375 ft
Type - Pset_ElementShading - Roughness: 3 ft
Type - Pset_ProductRequirements - Category: Walls
Type - Pset_QuantityTakeOff - Reference: Wall_4.5"
Type - Pset_ReinforcementBarPitchOfWall - Reference: Wall_4.5"
Type - Pset_WallCommon - IsExternal: no; Reference: Wall_4.5"
Classification: B2010 Exterior Walls (Uniformat)
Pset_QuantityTakeOff - sets with these values: 2
Pset_WallCommon - IsExternal: yes; ExtendToStructure: no; LoadBearing: no
Name (Basic Wall:Wall_4.5":...)
1448815
1449317
1449509
1449540
1449693
1450590
1450712
1450796
1450859
1451509
1452026
1452649
1452738
1452950
1453299
1453705
1453754
1454073
1454133
1454134
1454135
1454136
1454137
1454138
1454139
1454142
1454143
1454144
1454147
1454148
1454151
1454152
1454153
1454154
1510883
1512345
1512379

# IfcWallStandardCase: Basic Wall:Wall_5", Basic Wall:Wall_5":1454124
In: First floor
Type - PredefinedType: STANDARD; Material: Default New Material 0.416667 ft
Type - Pset_ElementShading - Roughness: 3 ft
Type - Pset_ProductRequirements - Category: Walls
Type - Pset_QuantityTakeOff - Reference: Wall_5"
Type - Pset_ReinforcementBarPitchOfWall - Reference: Wall_5"
Type - Pset_WallCommon - IsExternal: no; Reference: Wall_5"
Classification: B2010 Exterior Walls (Uniformat)
Pset_QuantityTakeOff - sets with these values: 2
Pset_WallCommon - IsExternal: yes; ExtendToStructure: no; LoadBearing: no

# IfcWallStandardCase: Basic Wall:Wall_5.5" (6)
In: First floor
Type - PredefinedType: STANDARD; Material: Default New Material 0.458333 ft
Type - Pset_ElementShading - Roughness: 3 ft
Type - Pset_ProductRequirements - Category: Walls
Type - Pset_QuantityTakeOff - Reference: Wall_5.5"
Type - Pset_ReinforcementBarPitchOfWall - Reference: Wall_5.5"
Type - Pset_WallCommon - IsExternal: no; Reference: Wall_5.5"
Classification: B2010 Exterior Walls (Uniformat)
Pset_QuantityTakeOff - sets with these values: 2
Pset_WallCommon - IsExternal: yes; ExtendToStructure: no; LoadBearing: no
Name (Basic Wall:Wall_5.5":...)
1448890
1450073
1451821
1453594
1453644
1454149

# IfcWallStandardCase: Basic Wall:Wall_6", Basic Wall:Wall_6":1454145
In: First floor
Type - PredefinedType: STANDARD; Material: Default New Material 0.5 ft
Type - Pset_ElementShading - Roughness: 1 ft
Type - Pset_ProductRequirements - Category: Walls
Type - Pset_QuantityTakeOff - Reference: Wall_6"
Type - Pset_ReinforcementBarPitchOfWall - Reference: Wall_6"
Type - Pset_WallCommon - IsExternal: no; Reference: Wall_6"
Pset_QuantityTakeOff - sets with these values: 2
Pset_WallCommon - IsExternal: yes; ExtendToStructure: no; LoadBearing: no

# IfcWallStandardCase: Basic Wall:Wall_6.5" (28)
In: First floor
Type - PredefinedType: STANDARD; Material: Default New Material 0.541667 ft
Type - Pset_ElementShading - Roughness: 3 ft
Type - Pset_ProductRequirements - Category: Walls
Type - Pset_QuantityTakeOff - Reference: Wall_6.5"
Type - Pset_ReinforcementBarPitchOfWall - Reference: Wall_6.5"
Type - Pset_WallCommon - Reference: Wall_6.5"; IsExternal: no
Classification: B2010 Exterior Walls (Uniformat)
Pset_QuantityTakeOff - sets with these values: 2
Pset_WallCommon - IsExternal: yes; ExtendToStructure: no; LoadBearing: no
Name (Basic Wall:Wall_6.5":...)
1447131
1447216
1447478
1447548
1447667
1447764
1448011
1448059
1448140
1448221
1448287
1448360
1448986
1449094
1449617
1449792
1450319
1450957
1451143
1451590
1453847
1453988
1454119
1454120
1454132
1454150
1459664
1676951

# IfcWallStandardCase: Basic Wall:Wall_6.75", Basic Wall:Wall_6.75":1453414
In: First floor
Type - PredefinedType: STANDARD; Material: Default New Material 0.5625 ft
Type - Pset_ElementShading - Roughness: 3 ft
Type - Pset_ProductRequirements - Category: Walls
Type - Pset_QuantityTakeOff - Reference: Wall_6.75"
Type - Pset_ReinforcementBarPitchOfWall - Reference: Wall_6.75"
Type - Pset_WallCommon - IsExternal: no; Reference: Wall_6.75"
Classification: B2010 Exterior Walls (Uniformat)
Pset_QuantityTakeOff - sets with these values: 2
Pset_WallCommon - IsExternal: yes; ExtendToStructure: no; LoadBearing: no

# IfcWallStandardCase: Basic Wall:Wall_7", Basic Wall:Wall_7":1450536
In: First floor
Type - PredefinedType: STANDARD; Material: Default New Material 0.583333 ft
Type - Pset_ElementShading - Roughness: 3 ft
Type - Pset_ProductRequirements - Category: Walls
Type - Pset_QuantityTakeOff - Reference: Wall_7"
Type - Pset_ReinforcementBarPitchOfWall - Reference: Wall_7"
Type - Pset_WallCommon - IsExternal: no; Reference: Wall_7"
Classification: B2010 Exterior Walls (Uniformat)
Pset_QuantityTakeOff - sets with these values: 2
Pset_WallCommon - IsExternal: yes; ExtendToStructure: no; LoadBearing: no

# IfcWallStandardCase: Basic Wall:Wall_7.5" (3)
In: First floor
Type - PredefinedType: STANDARD; Material: Default New Material 0.625 ft
Type - Pset_ElementShading - Roughness: 3 ft
Type - Pset_ProductRequirements - Category: Walls
Type - Pset_QuantityTakeOff - Reference: Wall_7.5"
Type - Pset_ReinforcementBarPitchOfWall - Reference: Wall_7.5"
Type - Pset_WallCommon - IsExternal: no; Reference: Wall_7.5"
Classification: B2010 Exterior Walls (Uniformat)
Pset_QuantityTakeOff - sets with these values: 2
Pset_WallCommon - IsExternal: yes; ExtendToStructure: no; LoadBearing: no
Name (Basic Wall:Wall_7.5":...)
1448645
1451682
1454117

# IfcWallStandardCase: Basic Wall:Wall_8" (7)
In: First floor
Type - PredefinedType: STANDARD; Material: Default New Material 0.666667 ft
Type - Pset_ElementShading - Roughness: 3 ft
Type - Pset_ProductRequirements - Category: Walls
Type - Pset_QuantityTakeOff - Reference: Wall_8"
Type - Pset_ReinforcementBarPitchOfWall - Reference: Wall_8"
Type - Pset_WallCommon - IsExternal: no; Reference: Wall_8"
Classification: B2010 Exterior Walls (Uniformat)
Pset_QuantityTakeOff - sets with these values: 2
Pset_WallCommon - IsExternal: yes; ExtendToStructure: no; LoadBearing: no
Name (Basic Wall:Wall_8":...)
1447331
1449872
1450214
1451245
1451280
1453042
1454122

# IfcWallStandardCase: Basic Wall:Wall_8.5" (5)
In: First floor
Type - PredefinedType: STANDARD; Material: Default New Material 0.708333 ft
Type - Pset_ElementShading - Roughness: 3 ft
Type - Pset_ProductRequirements - Category: Walls
Type - Pset_QuantityTakeOff - Reference: Wall_8.5"
Type - Pset_ReinforcementBarPitchOfWall - Reference: Wall_8.5"
Type - Pset_WallCommon - IsExternal: no; Reference: Wall_8.5"
Classification: B2010 Exterior Walls (Uniformat)
Pset_QuantityTakeOff - sets with these values: 2
Pset_WallCommon - IsExternal: yes; ExtendToStructure: no; LoadBearing: no
Name (Basic Wall:Wall_8.5":...)
1447874
1448483
1452463
1452879
1454126

# IfcWallStandardCase: Basic Wall:Wall_9", Basic Wall:Wall_9":1453939
In: First floor
Type - PredefinedType: STANDARD; Material: Default New Material 0.75 ft
Type - Pset_ElementShading - Roughness: 3 ft
Type - Pset_ProductRequirements - Category: Walls
Type - Pset_QuantityTakeOff - Reference: Wall_9"
Type - Pset_ReinforcementBarPitchOfWall - Reference: Wall_9"
Type - Pset_WallCommon - IsExternal: no; Reference: Wall_9"
Classification: B2010 Exterior Walls (Uniformat)
Pset_QuantityTakeOff - sets with these values: 2
Pset_WallCommon - IsExternal: yes; ExtendToStructure: no; LoadBearing: no

# IfcWindow: Window_10:8'-2" X 2'-4", Window_10:8'-2" X 2'-4":1487686
In: First floor
Type - ParameterTakesPrecedence: no; Sizeable: no; Classification: B2020100 Windows (Uniformat); Material: Glass, Default New Material (2)
Type - Pset_ProductRequirements - Category: Windows
Type - Pset_QuantityTakeOff - Reference: 8'-2" X 2'-4"
Type - Pset_WindowCommon - IsExternal: no; Reference: 8'-2" X 2'-4"; ThermalTransmittance: 3.6886 kg/K/s3
OverallHeight: 2.33333 ft; OverallWidth: 8.16667 ft; Material: Default New Material, Glass
Pset_WindowCommon - IsExternal: yes

# IfcWindow: Window_11:6'-4" X 5'-8", Window_11:6'-4" X 5'-8":1486150
In: First floor
Type - ParameterTakesPrecedence: no; Sizeable: no; Classification: B2020100 Windows (Uniformat); Material: Default New Material (2), Glass, Sash
Type - Pset_ProductRequirements - Category: Windows
Type - Pset_QuantityTakeOff - Reference: 6'-4" X 5'-8"
Type - Pset_WindowCommon - IsExternal: no; Reference: 6'-4" X 5'-8"; ThermalTransmittance: 3.6886 kg/K/s3
OverallHeight: 5.66667 ft; OverallWidth: 6.33333 ft; Material: Glass, Default New Material
Pset_WindowCommon - IsExternal: yes

# IfcWindow: Window_13:6'-8" X 5'-10", Window_13:6'-8" X 5'-10":1472092
In: First floor
Type - ParameterTakesPrecedence: no; Sizeable: no; Classification: B2020100 Windows (Uniformat); Material: Default New Material (2), Sash, Glass
Type - Pset_ProductRequirements - Category: Windows
Type - Pset_QuantityTakeOff - Reference: 6'-8" X 5'-10"
Type - Pset_WindowCommon - IsExternal: no; Reference: 6'-8" X 5'-10"; ThermalTransmittance: 3.6886 kg/K/s3
OverallHeight: 5.83333 ft; OverallWidth: 6.66667 ft; Material: Glass, Default New Material
Pset_WindowCommon - IsExternal: yes

# IfcWindow: Window_1:5'-10" X 4'-10", Window_1:5'-10" X 4'-10":1467811
In: First floor
Type - ParameterTakesPrecedence: no; Sizeable: no; Classification: B2020100 Windows (Uniformat); Material: Default New Material (2), Glass
Type - Pset_ProductRequirements - Category: Windows
Type - Pset_QuantityTakeOff - Reference: 5'-10" X 4'-10"
Type - Pset_WindowCommon - IsExternal: no; Reference: 5'-10" X 4'-10"; ThermalTransmittance: 3.6886 kg/K/s3
OverallHeight: 4.83333 ft; OverallWidth: 5.83333 ft; Material: Glass, Default New Material
Pset_WindowCommon - IsExternal: yes

# IfcWindow: Window_2:4'-8" X 3'-10", Window_2:4'-8" X 3'-10":1471122
In: First floor
Type - ParameterTakesPrecedence: no; Sizeable: no; Classification: B2020100 Windows (Uniformat); Material: Default New Material (2), Sash, Glass
Type - Pset_ProductRequirements - Category: Windows
Type - Pset_QuantityTakeOff - Reference: 4'-8" X 3'-10"
Type - Pset_WindowCommon - IsExternal: no; Reference: 4'-8" X 3'-10"; ThermalTransmittance: 3.6886 kg/K/s3
OverallHeight: 3.83333 ft; OverallWidth: 4.66667 ft; Material: Glass, Default New Material
Pset_WindowCommon - IsExternal: yes

# IfcWindow: Window_3:12'-6" X 5'-10", Window_3:12'-6" X 5'-10":1472062
In: First floor
Type - ParameterTakesPrecedence: no; Sizeable: no; Classification: B2020100 Windows (Uniformat); Material: Glass, Sash, Default New Material (2)
Type - Pset_ProductRequirements - Category: Windows
Type - Pset_QuantityTakeOff - Reference: 12'-6" X 5'-10"
Type - Pset_WindowCommon - IsExternal: no; Reference: 12'-6" X 5'-10"; ThermalTransmittance: 3.6886 kg/K/s3
OverallHeight: 5.83333 ft; OverallWidth: 12.5 ft; Material: Glass, Default New Material
Pset_WindowCommon - IsExternal: yes

# IfcWindow: Window_4:1'-10" X 3'-10", Window_4:1'-10" X 3'-10":1485012
In: First floor
Type - ParameterTakesPrecedence: no; Sizeable: no; Classification: B2020100 Windows (Uniformat); Material: Sash, Trim (2), Glass
Type - Window_4:1'-10" X 3'-10":1485012 - MullionThickness: 0.0494792 ft
Type - Pset_ProductRequirements - Category: Windows
Type - Pset_QuantityTakeOff - Reference: 1'-10" X 3'-10"
Type - Pset_WindowCommon - IsExternal: no; Reference: 1'-10" X 3'-10"; ThermalTransmittance: 3.6886 kg/K/s3
OverallHeight: 3.83333 ft; OverallWidth: 1.83333 ft; Material: Glass, Default New Material
Pset_WindowCommon - IsExternal: yes

# IfcWindow: Window_4:2'-0" X 3'-10" (3)
In: First floor
Type - ParameterTakesPrecedence: no; Sizeable: no; Classification: B2020100 Windows (Uniformat); Material: Trim (2), Glass, Sash
Type - Window_4:2'-0" X 3'-10":1470228 - MullionThickness: 0.0494792 ft
Type - Pset_ProductRequirements - Category: Windows
Type - Pset_QuantityTakeOff - Reference: 2'-0" X 3'-10"
Type - Pset_WindowCommon - IsExternal: no; Reference: 2'-0" X 3'-10"; ThermalTransmittance: 3.6886 kg/K/s3
OverallHeight: 3.83333 ft; OverallWidth: 2 ft; Material: Glass, Default New Material
Pset_WindowCommon - IsExternal: yes
Name (Window_4:2'-0" X 3'-10":...)
1470228
1471126
1471128

# IfcWindow: Window_4:2'-10" X 4'-10", Window_4:2'-10" X 4'-10":1467646
In: First floor
Type - ParameterTakesPrecedence: no; Sizeable: no; Classification: B2020100 Windows (Uniformat); Material: Glass, Trim (2), Sash, Default New Material
Type - Window_4:2'-10" X 4'-10":1467646 - MullionThickness: 0.0494792 ft
Type - Pset_ProductRequirements - Category: Windows
Type - Pset_QuantityTakeOff - Reference: 2'-10" X 4'-10"
Type - Pset_WindowCommon - IsExternal: no; Reference: 2'-10" X 4'-10"; ThermalTransmittance: 3.6886 kg/K/s3
OverallHeight: 4.83333 ft; OverallWidth: 2.83333 ft; Material: Default New Material, Glass
Pset_WindowCommon - IsExternal: yes

# IfcWindow: Window_4:2'-10" X 4'-10", Window_4:2'-10" X 4'-10":1468012
In: First floor
Type - ParameterTakesPrecedence: no; Sizeable: no; Classification: B2020100 Windows (Uniformat); Material: Glass, Trim (2), Sash, Default New Material
Type - Window_4:2'-10" X 4'-10":1468012 - MullionThickness: 0.0494792 ft
Type - Pset_ProductRequirements - Category: Windows
Type - Pset_QuantityTakeOff - Reference: 2'-10" X 4'-10"
Type - Pset_WindowCommon - IsExternal: no; Reference: 2'-10" X 4'-10"; ThermalTransmittance: 3.6886 kg/K/s3
OverallHeight: 4.83333 ft; OverallWidth: 2.83333 ft; Material: Default New Material, Glass
Pset_WindowCommon - IsExternal: yes

# IfcWindow: Window_4:2'-4" X 3'-10", Window_4:2'-4" X 3'-10":1460397
In: First floor
Type - ParameterTakesPrecedence: no; Sizeable: no; Classification: B2020100 Windows (Uniformat); Material: Trim (2), Glass, Sash
Type - Window_4:2'-4" X 3'-10":1460397 - MullionThickness: 0.0494792 ft
Type - Pset_ProductRequirements - Category: Windows
Type - Pset_QuantityTakeOff - Reference: 2'-4" X 3'-10"
Type - Pset_WindowCommon - IsExternal: no; Reference: 2'-4" X 3'-10"; ThermalTransmittance: 3.6886 kg/K/s3
OverallHeight: 3.83333 ft; OverallWidth: 2.33333 ft; Material: Glass, Default New Material
Pset_WindowCommon - IsExternal: yes

# IfcWindow: Window_4:2'-6" X 5'-10", Window_4:2'-6" X 5'-10":1489094
In: First floor
Type - ParameterTakesPrecedence: no; Sizeable: no; Classification: B2020100 Windows (Uniformat); Material: Trim (2), Sash, Glass
Type - Window_4:2'-6" X 5'-10":1489094 - MullionThickness: 0.0494792 ft
Type - Pset_ProductRequirements - Category: Windows
Type - Pset_QuantityTakeOff - Reference: 2'-6" X 5'-10"
Type - Pset_WindowCommon - IsExternal: no; Reference: 2'-6" X 5'-10"; ThermalTransmittance: 3.6886 kg/K/s3
OverallHeight: 5.83333 ft; OverallWidth: 2.5 ft; Material: Glass, Default New Material
Pset_WindowCommon - IsExternal: yes

# IfcWindow: Window_5:2'-6" X 2'-6" (3)
In: First floor
Type - ParameterTakesPrecedence: no; Sizeable: no; Classification: B2020100 Windows (Uniformat); Material: Glass
Type - Pset_ProductRequirements - Category: Windows
Type - Pset_QuantityTakeOff - Reference: 2'-6" X 2'-6"
Type - Pset_WindowCommon - IsExternal: no; Reference: 2'-6" X 2'-6"; ThermalTransmittance: 3.6886 kg/K/s3
OverallHeight: 2.5 ft; OverallWidth: 2.5 ft; Material: Glass, Default New Material
Pset_WindowCommon - IsExternal: yes
Name (Window_5:2'-6" X 2'-6":...)
1633320
1635432
1635560

# IfcWindow: Window_6:3'-10" X 4'-0", Window_6:3'-10" X 4'-0":1468910
In: First floor
Type - ParameterTakesPrecedence: no; Sizeable: no; Classification: B2020100 Windows (Uniformat); Material: Default New Material (2), Glass
Type - Pset_ProductRequirements - Category: Windows
Type - Pset_QuantityTakeOff - Reference: 3'-10" X 4'-0"
Type - Pset_WindowCommon - IsExternal: no; Reference: 3'-10" X 4'-0"; ThermalTransmittance: 3.6886 kg/K/s3
OverallHeight: 4 ft; OverallWidth: 3.83333 ft; Material: Glass, Default New Material
Pset_WindowCommon - IsExternal: yes

# IfcWindow: Window_6:3'-8" X 3'-8", Window_6:3'-8" X 3'-8":1461024
In: First floor
Type - ParameterTakesPrecedence: no; Sizeable: no; Classification: B2020100 Windows (Uniformat); Material: Glass, Default New Material (2)
Type - Pset_ProductRequirements - Category: Windows
Type - Pset_QuantityTakeOff - Reference: 3'-8" X 3'-8"
Type - Pset_WindowCommon - IsExternal: no; Reference: 3'-8" X 3'-8"; ThermalTransmittance: 3.6886 kg/K/s3
OverallHeight: 3.66667 ft; OverallWidth: 3.66667 ft; Material: Glass, Default New Material
Pset_WindowCommon - IsExternal: yes

# IfcWindow: Window_7:5'-0" X 4'-8", Window_7:5'-0" X 4'-8":1469384
In: First floor
Type - ParameterTakesPrecedence: no; Sizeable: no; Classification: B2020100 Windows (Uniformat); Material: Glass, Default New Material (2)
Type - Pset_ProductRequirements - Category: Windows
Type - Pset_QuantityTakeOff - Reference: 5'-0" X 4'-8"
Type - Pset_WindowCommon - IsExternal: no; Reference: 5'-0" X 4'-8"; ThermalTransmittance: 3.6886 kg/K/s3
OverallHeight: 4.66667 ft; OverallWidth: 5 ft; Material: Glass, Default New Material
Pset_WindowCommon - IsExternal: yes

# IfcWindow: Window_8:2'-6" X 2'-6" (2)
In: First floor
Type - ParameterTakesPrecedence: no; Sizeable: no; Classification: B2020100 Windows (Uniformat); Material: Glass, Default New Material (2)
Type - Pset_ProductRequirements - Category: Windows
Type - Pset_QuantityTakeOff - Reference: 2'-6" X 2'-6"
Type - Pset_WindowCommon - IsExternal: no; Reference: 2'-6" X 2'-6"; ThermalTransmittance: 3.6886 kg/K/s3
OverallHeight: 2.5 ft; OverallWidth: 2.5 ft; Material: Glass, Default New Material
Pset_WindowCommon - IsExternal: yes
Name (Window_8:2'-6" X 2'-6":...)
1472989
1481301

# IfcWindow: Window_9:5'-6" X 4'-8", Window_9:5'-6" X 4'-8":1487284
In: First floor
Type - ParameterTakesPrecedence: no; Sizeable: no; Classification: B2020100 Windows (Uniformat); Material: Default New Material (2), Glass
Type - Pset_ProductRequirements - Category: Windows
Type - Pset_QuantityTakeOff - Reference: 5'-6" X 4'-8"
Type - Pset_WindowCommon - IsExternal: no; Reference: 5'-6" X 4'-8"; ThermalTransmittance: 3.6886 kg/K/s3
OverallHeight: 4.66667 ft; OverallWidth: 5.5 ft; Material: Default New Material, Glass
Pset_WindowCommon - IsExternal: yes
